VERSION 5.8 ;
BUSBITCHARS "[]" ;
DIVIDERCHAR "/" ;
UNITS
    DATABASE MICRONS 1000 ;
END UNITS

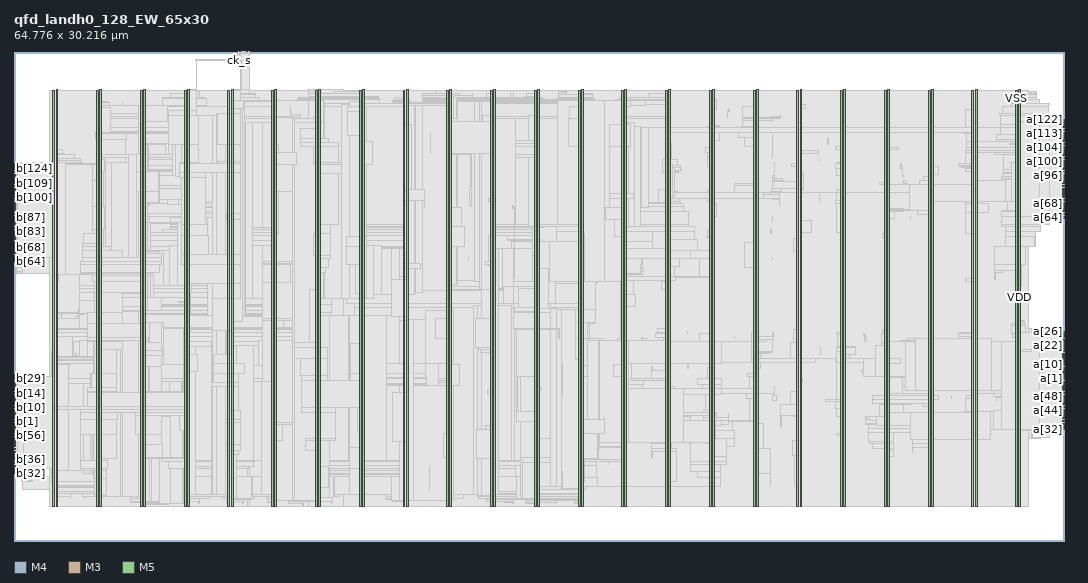
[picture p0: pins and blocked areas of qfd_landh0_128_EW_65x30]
MACRO qfd_landh0_128_EW_65x30
  FOREIGN qfd_landh0_128_EW_65x30 0 0 ;
  CLASS BLOCK ;
  SIZE 64.776 BY 30.216 ;
  PIN a[0]
    DIRECTION INPUT ;
    USE SIGNAL ;
    PORT
      LAYER M4 ;
        RECT  64.692 9.936 64.776 9.96 ;
    END
  END a[0]
  PIN a[100]
    DIRECTION INPUT ;
    USE SIGNAL ;
    PORT
      LAYER M4 ;
        RECT  64.692 23.376 64.776 23.4 ;
    END
  END a[100]
  PIN a[101]
    DIRECTION INPUT ;
    USE SIGNAL ;
    PORT
      LAYER M4 ;
        RECT  64.692 23.472 64.776 23.496 ;
    END
  END a[101]
  PIN a[102]
    DIRECTION INPUT ;
    USE SIGNAL ;
    PORT
      LAYER M4 ;
        RECT  64.692 23.568 64.776 23.592 ;
    END
  END a[102]
  PIN a[103]
    DIRECTION INPUT ;
    USE SIGNAL ;
    PORT
      LAYER M4 ;
        RECT  64.692 23.664 64.776 23.688 ;
    END
  END a[103]
  PIN a[104]
    DIRECTION INPUT ;
    USE SIGNAL ;
    PORT
      LAYER M4 ;
        RECT  64.692 23.76 64.776 23.784 ;
    END
  END a[104]
  PIN a[105]
    DIRECTION INPUT ;
    USE SIGNAL ;
    PORT
      LAYER M4 ;
        RECT  64.692 23.856 64.776 23.88 ;
    END
  END a[105]
  PIN a[106]
    DIRECTION INPUT ;
    USE SIGNAL ;
    PORT
      LAYER M4 ;
        RECT  64.692 23.952 64.776 23.976 ;
    END
  END a[106]
  PIN a[107]
    DIRECTION INPUT ;
    USE SIGNAL ;
    PORT
      LAYER M4 ;
        RECT  64.692 24.048 64.776 24.072 ;
    END
  END a[107]
  PIN a[108]
    DIRECTION INPUT ;
    USE SIGNAL ;
    PORT
      LAYER M4 ;
        RECT  64.692 24.144 64.776 24.168 ;
    END
  END a[108]
  PIN a[109]
    DIRECTION INPUT ;
    USE SIGNAL ;
    PORT
      LAYER M4 ;
        RECT  64.692 24.24 64.776 24.264 ;
    END
  END a[109]
  PIN a[10]
    DIRECTION INPUT ;
    USE SIGNAL ;
    PORT
      LAYER M4 ;
        RECT  64.692 10.896 64.776 10.92 ;
    END
  END a[10]
  PIN a[110]
    DIRECTION INPUT ;
    USE SIGNAL ;
    PORT
      LAYER M4 ;
        RECT  64.692 24.336 64.776 24.36 ;
    END
  END a[110]
  PIN a[111]
    DIRECTION INPUT ;
    USE SIGNAL ;
    PORT
      LAYER M4 ;
        RECT  64.692 24.432 64.776 24.456 ;
    END
  END a[111]
  PIN a[112]
    DIRECTION INPUT ;
    USE SIGNAL ;
    PORT
      LAYER M4 ;
        RECT  64.692 24.528 64.776 24.552 ;
    END
  END a[112]
  PIN a[113]
    DIRECTION INPUT ;
    USE SIGNAL ;
    PORT
      LAYER M4 ;
        RECT  64.692 24.624 64.776 24.648 ;
    END
  END a[113]
  PIN a[114]
    DIRECTION INPUT ;
    USE SIGNAL ;
    PORT
      LAYER M4 ;
        RECT  64.692 24.72 64.776 24.744 ;
    END
  END a[114]
  PIN a[115]
    DIRECTION INPUT ;
    USE SIGNAL ;
    PORT
      LAYER M4 ;
        RECT  64.692 24.816 64.776 24.84 ;
    END
  END a[115]
  PIN a[116]
    DIRECTION INPUT ;
    USE SIGNAL ;
    PORT
      LAYER M4 ;
        RECT  64.692 24.912 64.776 24.936 ;
    END
  END a[116]
  PIN a[117]
    DIRECTION INPUT ;
    USE SIGNAL ;
    PORT
      LAYER M4 ;
        RECT  64.692 25.008 64.776 25.032 ;
    END
  END a[117]
  PIN a[118]
    DIRECTION INPUT ;
    USE SIGNAL ;
    PORT
      LAYER M4 ;
        RECT  64.692 25.104 64.776 25.128 ;
    END
  END a[118]
  PIN a[119]
    DIRECTION INPUT ;
    USE SIGNAL ;
    PORT
      LAYER M4 ;
        RECT  64.692 25.2 64.776 25.224 ;
    END
  END a[119]
  PIN a[11]
    DIRECTION INPUT ;
    USE SIGNAL ;
    PORT
      LAYER M4 ;
        RECT  64.692 10.992 64.776 11.016 ;
    END
  END a[11]
  PIN a[120]
    DIRECTION INPUT ;
    USE SIGNAL ;
    PORT
      LAYER M4 ;
        RECT  64.692 25.296 64.776 25.32 ;
    END
  END a[120]
  PIN a[121]
    DIRECTION INPUT ;
    USE SIGNAL ;
    PORT
      LAYER M4 ;
        RECT  64.692 25.392 64.776 25.416 ;
    END
  END a[121]
  PIN a[122]
    DIRECTION INPUT ;
    USE SIGNAL ;
    PORT
      LAYER M4 ;
        RECT  64.692 25.488 64.776 25.512 ;
    END
  END a[122]
  PIN a[123]
    DIRECTION INPUT ;
    USE SIGNAL ;
    PORT
      LAYER M4 ;
        RECT  64.692 25.584 64.776 25.608 ;
    END
  END a[123]
  PIN a[124]
    DIRECTION INPUT ;
    USE SIGNAL ;
    PORT
      LAYER M4 ;
        RECT  64.692 25.68 64.776 25.704 ;
    END
  END a[124]
  PIN a[125]
    DIRECTION INPUT ;
    USE SIGNAL ;
    PORT
      LAYER M4 ;
        RECT  64.692 25.776 64.776 25.8 ;
    END
  END a[125]
  PIN a[126]
    DIRECTION INPUT ;
    USE SIGNAL ;
    PORT
      LAYER M4 ;
        RECT  64.692 25.872 64.776 25.896 ;
    END
  END a[126]
  PIN a[127]
    DIRECTION INPUT ;
    USE SIGNAL ;
    PORT
      LAYER M4 ;
        RECT  64.692 25.968 64.776 25.992 ;
    END
  END a[127]
  PIN a[12]
    DIRECTION INPUT ;
    USE SIGNAL ;
    PORT
      LAYER M4 ;
        RECT  64.692 11.088 64.776 11.112 ;
    END
  END a[12]
  PIN a[13]
    DIRECTION INPUT ;
    USE SIGNAL ;
    PORT
      LAYER M4 ;
        RECT  64.692 11.184 64.776 11.208 ;
    END
  END a[13]
  PIN a[14]
    DIRECTION INPUT ;
    USE SIGNAL ;
    PORT
      LAYER M4 ;
        RECT  64.692 11.28 64.776 11.304 ;
    END
  END a[14]
  PIN a[15]
    DIRECTION INPUT ;
    USE SIGNAL ;
    PORT
      LAYER M4 ;
        RECT  64.692 11.376 64.776 11.4 ;
    END
  END a[15]
  PIN a[16]
    DIRECTION INPUT ;
    USE SIGNAL ;
    PORT
      LAYER M4 ;
        RECT  64.692 11.472 64.776 11.496 ;
    END
  END a[16]
  PIN a[17]
    DIRECTION INPUT ;
    USE SIGNAL ;
    PORT
      LAYER M4 ;
        RECT  64.692 11.568 64.776 11.592 ;
    END
  END a[17]
  PIN a[18]
    DIRECTION INPUT ;
    USE SIGNAL ;
    PORT
      LAYER M4 ;
        RECT  64.692 11.664 64.776 11.688 ;
    END
  END a[18]
  PIN a[19]
    DIRECTION INPUT ;
    USE SIGNAL ;
    PORT
      LAYER M4 ;
        RECT  64.692 11.76 64.776 11.784 ;
    END
  END a[19]
  PIN a[1]
    DIRECTION INPUT ;
    USE SIGNAL ;
    PORT
      LAYER M4 ;
        RECT  64.692 10.032 64.776 10.056 ;
    END
  END a[1]
  PIN a[20]
    DIRECTION INPUT ;
    USE SIGNAL ;
    PORT
      LAYER M4 ;
        RECT  64.692 11.856 64.776 11.88 ;
    END
  END a[20]
  PIN a[21]
    DIRECTION INPUT ;
    USE SIGNAL ;
    PORT
      LAYER M4 ;
        RECT  64.692 11.952 64.776 11.976 ;
    END
  END a[21]
  PIN a[22]
    DIRECTION INPUT ;
    USE SIGNAL ;
    PORT
      LAYER M4 ;
        RECT  64.692 12.048 64.776 12.072 ;
    END
  END a[22]
  PIN a[23]
    DIRECTION INPUT ;
    USE SIGNAL ;
    PORT
      LAYER M4 ;
        RECT  64.692 12.144 64.776 12.168 ;
    END
  END a[23]
  PIN a[24]
    DIRECTION INPUT ;
    USE SIGNAL ;
    PORT
      LAYER M4 ;
        RECT  64.692 12.24 64.776 12.264 ;
    END
  END a[24]
  PIN a[25]
    DIRECTION INPUT ;
    USE SIGNAL ;
    PORT
      LAYER M4 ;
        RECT  64.692 12.336 64.776 12.36 ;
    END
  END a[25]
  PIN a[26]
    DIRECTION INPUT ;
    USE SIGNAL ;
    PORT
      LAYER M4 ;
        RECT  64.692 12.432 64.776 12.456 ;
    END
  END a[26]
  PIN a[27]
    DIRECTION INPUT ;
    USE SIGNAL ;
    PORT
      LAYER M4 ;
        RECT  64.692 12.528 64.776 12.552 ;
    END
  END a[27]
  PIN a[28]
    DIRECTION INPUT ;
    USE SIGNAL ;
    PORT
      LAYER M4 ;
        RECT  64.692 12.624 64.776 12.648 ;
    END
  END a[28]
  PIN a[29]
    DIRECTION INPUT ;
    USE SIGNAL ;
    PORT
      LAYER M4 ;
        RECT  64.692 12.72 64.776 12.744 ;
    END
  END a[29]
  PIN a[2]
    DIRECTION INPUT ;
    USE SIGNAL ;
    PORT
      LAYER M4 ;
        RECT  64.692 10.128 64.776 10.152 ;
    END
  END a[2]
  PIN a[30]
    DIRECTION INPUT ;
    USE SIGNAL ;
    PORT
      LAYER M4 ;
        RECT  64.692 12.816 64.776 12.84 ;
    END
  END a[30]
  PIN a[31]
    DIRECTION INPUT ;
    USE SIGNAL ;
    PORT
      LAYER M4 ;
        RECT  64.692 12.912 64.776 12.936 ;
    END
  END a[31]
  PIN a[32]
    DIRECTION INPUT ;
    USE SIGNAL ;
    PORT
      LAYER M4 ;
        RECT  64.692 6.864 64.776 6.888 ;
    END
  END a[32]
  PIN a[33]
    DIRECTION INPUT ;
    USE SIGNAL ;
    PORT
      LAYER M4 ;
        RECT  64.692 6.96 64.776 6.984 ;
    END
  END a[33]
  PIN a[34]
    DIRECTION INPUT ;
    USE SIGNAL ;
    PORT
      LAYER M4 ;
        RECT  64.692 7.056 64.776 7.08 ;
    END
  END a[34]
  PIN a[35]
    DIRECTION INPUT ;
    USE SIGNAL ;
    PORT
      LAYER M4 ;
        RECT  64.692 7.152 64.776 7.176 ;
    END
  END a[35]
  PIN a[36]
    DIRECTION INPUT ;
    USE SIGNAL ;
    PORT
      LAYER M4 ;
        RECT  64.692 7.248 64.776 7.272 ;
    END
  END a[36]
  PIN a[37]
    DIRECTION INPUT ;
    USE SIGNAL ;
    PORT
      LAYER M4 ;
        RECT  64.692 7.344 64.776 7.368 ;
    END
  END a[37]
  PIN a[38]
    DIRECTION INPUT ;
    USE SIGNAL ;
    PORT
      LAYER M4 ;
        RECT  64.692 7.44 64.776 7.464 ;
    END
  END a[38]
  PIN a[39]
    DIRECTION INPUT ;
    USE SIGNAL ;
    PORT
      LAYER M4 ;
        RECT  64.692 7.536 64.776 7.56 ;
    END
  END a[39]
  PIN a[3]
    DIRECTION INPUT ;
    USE SIGNAL ;
    PORT
      LAYER M4 ;
        RECT  64.692 10.224 64.776 10.248 ;
    END
  END a[3]
  PIN a[40]
    DIRECTION INPUT ;
    USE SIGNAL ;
    PORT
      LAYER M4 ;
        RECT  64.692 7.632 64.776 7.656 ;
    END
  END a[40]
  PIN a[41]
    DIRECTION INPUT ;
    USE SIGNAL ;
    PORT
      LAYER M4 ;
        RECT  64.692 7.728 64.776 7.752 ;
    END
  END a[41]
  PIN a[42]
    DIRECTION INPUT ;
    USE SIGNAL ;
    PORT
      LAYER M4 ;
        RECT  64.692 7.824 64.776 7.848 ;
    END
  END a[42]
  PIN a[43]
    DIRECTION INPUT ;
    USE SIGNAL ;
    PORT
      LAYER M4 ;
        RECT  64.692 7.92 64.776 7.944 ;
    END
  END a[43]
  PIN a[44]
    DIRECTION INPUT ;
    USE SIGNAL ;
    PORT
      LAYER M4 ;
        RECT  64.692 8.016 64.776 8.04 ;
    END
  END a[44]
  PIN a[45]
    DIRECTION INPUT ;
    USE SIGNAL ;
    PORT
      LAYER M4 ;
        RECT  64.692 8.112 64.776 8.136 ;
    END
  END a[45]
  PIN a[46]
    DIRECTION INPUT ;
    USE SIGNAL ;
    PORT
      LAYER M4 ;
        RECT  64.692 8.208 64.776 8.232 ;
    END
  END a[46]
  PIN a[47]
    DIRECTION INPUT ;
    USE SIGNAL ;
    PORT
      LAYER M4 ;
        RECT  64.692 8.304 64.776 8.328 ;
    END
  END a[47]
  PIN a[48]
    DIRECTION INPUT ;
    USE SIGNAL ;
    PORT
      LAYER M4 ;
        RECT  64.692 8.4 64.776 8.424 ;
    END
  END a[48]
  PIN a[49]
    DIRECTION INPUT ;
    USE SIGNAL ;
    PORT
      LAYER M4 ;
        RECT  64.692 8.496 64.776 8.52 ;
    END
  END a[49]
  PIN a[4]
    DIRECTION INPUT ;
    USE SIGNAL ;
    PORT
      LAYER M4 ;
        RECT  64.692 10.32 64.776 10.344 ;
    END
  END a[4]
  PIN a[50]
    DIRECTION INPUT ;
    USE SIGNAL ;
    PORT
      LAYER M4 ;
        RECT  64.692 8.592 64.776 8.616 ;
    END
  END a[50]
  PIN a[51]
    DIRECTION INPUT ;
    USE SIGNAL ;
    PORT
      LAYER M4 ;
        RECT  64.692 8.688 64.776 8.712 ;
    END
  END a[51]
  PIN a[52]
    DIRECTION INPUT ;
    USE SIGNAL ;
    PORT
      LAYER M4 ;
        RECT  64.692 8.784 64.776 8.808 ;
    END
  END a[52]
  PIN a[53]
    DIRECTION INPUT ;
    USE SIGNAL ;
    PORT
      LAYER M4 ;
        RECT  64.692 8.88 64.776 8.904 ;
    END
  END a[53]
  PIN a[54]
    DIRECTION INPUT ;
    USE SIGNAL ;
    PORT
      LAYER M4 ;
        RECT  64.692 8.976 64.776 9 ;
    END
  END a[54]
  PIN a[55]
    DIRECTION INPUT ;
    USE SIGNAL ;
    PORT
      LAYER M4 ;
        RECT  64.692 9.072 64.776 9.096 ;
    END
  END a[55]
  PIN a[56]
    DIRECTION INPUT ;
    USE SIGNAL ;
    PORT
      LAYER M4 ;
        RECT  64.692 9.168 64.776 9.192 ;
    END
  END a[56]
  PIN a[57]
    DIRECTION INPUT ;
    USE SIGNAL ;
    PORT
      LAYER M4 ;
        RECT  64.692 9.264 64.776 9.288 ;
    END
  END a[57]
  PIN a[58]
    DIRECTION INPUT ;
    USE SIGNAL ;
    PORT
      LAYER M4 ;
        RECT  64.692 9.36 64.776 9.384 ;
    END
  END a[58]
  PIN a[59]
    DIRECTION INPUT ;
    USE SIGNAL ;
    PORT
      LAYER M4 ;
        RECT  64.692 9.456 64.776 9.48 ;
    END
  END a[59]
  PIN a[5]
    DIRECTION INPUT ;
    USE SIGNAL ;
    PORT
      LAYER M4 ;
        RECT  64.692 10.416 64.776 10.44 ;
    END
  END a[5]
  PIN a[60]
    DIRECTION INPUT ;
    USE SIGNAL ;
    PORT
      LAYER M4 ;
        RECT  64.692 9.552 64.776 9.576 ;
    END
  END a[60]
  PIN a[61]
    DIRECTION INPUT ;
    USE SIGNAL ;
    PORT
      LAYER M4 ;
        RECT  64.692 9.648 64.776 9.672 ;
    END
  END a[61]
  PIN a[62]
    DIRECTION INPUT ;
    USE SIGNAL ;
    PORT
      LAYER M4 ;
        RECT  64.692 9.744 64.776 9.768 ;
    END
  END a[62]
  PIN a[63]
    DIRECTION INPUT ;
    USE SIGNAL ;
    PORT
      LAYER M4 ;
        RECT  64.692 9.84 64.776 9.864 ;
    END
  END a[63]
  PIN a[64]
    DIRECTION INPUT ;
    USE SIGNAL ;
    PORT
      LAYER M4 ;
        RECT  64.692 19.92 64.776 19.944 ;
    END
  END a[64]
  PIN a[65]
    DIRECTION INPUT ;
    USE SIGNAL ;
    PORT
      LAYER M4 ;
        RECT  64.692 20.016 64.776 20.04 ;
    END
  END a[65]
  PIN a[66]
    DIRECTION INPUT ;
    USE SIGNAL ;
    PORT
      LAYER M4 ;
        RECT  64.692 20.112 64.776 20.136 ;
    END
  END a[66]
  PIN a[67]
    DIRECTION INPUT ;
    USE SIGNAL ;
    PORT
      LAYER M4 ;
        RECT  64.692 20.208 64.776 20.232 ;
    END
  END a[67]
  PIN a[68]
    DIRECTION INPUT ;
    USE SIGNAL ;
    PORT
      LAYER M4 ;
        RECT  64.692 20.304 64.776 20.328 ;
    END
  END a[68]
  PIN a[69]
    DIRECTION INPUT ;
    USE SIGNAL ;
    PORT
      LAYER M4 ;
        RECT  64.692 20.4 64.776 20.424 ;
    END
  END a[69]
  PIN a[6]
    DIRECTION INPUT ;
    USE SIGNAL ;
    PORT
      LAYER M4 ;
        RECT  64.692 10.512 64.776 10.536 ;
    END
  END a[6]
  PIN a[70]
    DIRECTION INPUT ;
    USE SIGNAL ;
    PORT
      LAYER M4 ;
        RECT  64.692 20.496 64.776 20.52 ;
    END
  END a[70]
  PIN a[71]
    DIRECTION INPUT ;
    USE SIGNAL ;
    PORT
      LAYER M4 ;
        RECT  64.692 20.592 64.776 20.616 ;
    END
  END a[71]
  PIN a[72]
    DIRECTION INPUT ;
    USE SIGNAL ;
    PORT
      LAYER M4 ;
        RECT  64.692 20.688 64.776 20.712 ;
    END
  END a[72]
  PIN a[73]
    DIRECTION INPUT ;
    USE SIGNAL ;
    PORT
      LAYER M4 ;
        RECT  64.692 20.784 64.776 20.808 ;
    END
  END a[73]
  PIN a[74]
    DIRECTION INPUT ;
    USE SIGNAL ;
    PORT
      LAYER M4 ;
        RECT  64.692 20.88 64.776 20.904 ;
    END
  END a[74]
  PIN a[75]
    DIRECTION INPUT ;
    USE SIGNAL ;
    PORT
      LAYER M4 ;
        RECT  64.692 20.976 64.776 21 ;
    END
  END a[75]
  PIN a[76]
    DIRECTION INPUT ;
    USE SIGNAL ;
    PORT
      LAYER M4 ;
        RECT  64.692 21.072 64.776 21.096 ;
    END
  END a[76]
  PIN a[77]
    DIRECTION INPUT ;
    USE SIGNAL ;
    PORT
      LAYER M4 ;
        RECT  64.692 21.168 64.776 21.192 ;
    END
  END a[77]
  PIN a[78]
    DIRECTION INPUT ;
    USE SIGNAL ;
    PORT
      LAYER M4 ;
        RECT  64.692 21.264 64.776 21.288 ;
    END
  END a[78]
  PIN a[79]
    DIRECTION INPUT ;
    USE SIGNAL ;
    PORT
      LAYER M4 ;
        RECT  64.692 21.36 64.776 21.384 ;
    END
  END a[79]
  PIN a[7]
    DIRECTION INPUT ;
    USE SIGNAL ;
    PORT
      LAYER M4 ;
        RECT  64.692 10.608 64.776 10.632 ;
    END
  END a[7]
  PIN a[80]
    DIRECTION INPUT ;
    USE SIGNAL ;
    PORT
      LAYER M4 ;
        RECT  64.692 21.456 64.776 21.48 ;
    END
  END a[80]
  PIN a[81]
    DIRECTION INPUT ;
    USE SIGNAL ;
    PORT
      LAYER M4 ;
        RECT  64.692 21.552 64.776 21.576 ;
    END
  END a[81]
  PIN a[82]
    DIRECTION INPUT ;
    USE SIGNAL ;
    PORT
      LAYER M4 ;
        RECT  64.692 21.648 64.776 21.672 ;
    END
  END a[82]
  PIN a[83]
    DIRECTION INPUT ;
    USE SIGNAL ;
    PORT
      LAYER M4 ;
        RECT  64.692 21.744 64.776 21.768 ;
    END
  END a[83]
  PIN a[84]
    DIRECTION INPUT ;
    USE SIGNAL ;
    PORT
      LAYER M4 ;
        RECT  64.692 21.84 64.776 21.864 ;
    END
  END a[84]
  PIN a[85]
    DIRECTION INPUT ;
    USE SIGNAL ;
    PORT
      LAYER M4 ;
        RECT  64.692 21.936 64.776 21.96 ;
    END
  END a[85]
  PIN a[86]
    DIRECTION INPUT ;
    USE SIGNAL ;
    PORT
      LAYER M4 ;
        RECT  64.692 22.032 64.776 22.056 ;
    END
  END a[86]
  PIN a[87]
    DIRECTION INPUT ;
    USE SIGNAL ;
    PORT
      LAYER M4 ;
        RECT  64.692 22.128 64.776 22.152 ;
    END
  END a[87]
  PIN a[88]
    DIRECTION INPUT ;
    USE SIGNAL ;
    PORT
      LAYER M4 ;
        RECT  64.692 22.224 64.776 22.248 ;
    END
  END a[88]
  PIN a[89]
    DIRECTION INPUT ;
    USE SIGNAL ;
    PORT
      LAYER M4 ;
        RECT  64.692 22.32 64.776 22.344 ;
    END
  END a[89]
  PIN a[8]
    DIRECTION INPUT ;
    USE SIGNAL ;
    PORT
      LAYER M4 ;
        RECT  64.692 10.704 64.776 10.728 ;
    END
  END a[8]
  PIN a[90]
    DIRECTION INPUT ;
    USE SIGNAL ;
    PORT
      LAYER M4 ;
        RECT  64.692 22.416 64.776 22.44 ;
    END
  END a[90]
  PIN a[91]
    DIRECTION INPUT ;
    USE SIGNAL ;
    PORT
      LAYER M4 ;
        RECT  64.692 22.512 64.776 22.536 ;
    END
  END a[91]
  PIN a[92]
    DIRECTION INPUT ;
    USE SIGNAL ;
    PORT
      LAYER M4 ;
        RECT  64.692 22.608 64.776 22.632 ;
    END
  END a[92]
  PIN a[93]
    DIRECTION INPUT ;
    USE SIGNAL ;
    PORT
      LAYER M4 ;
        RECT  64.692 22.704 64.776 22.728 ;
    END
  END a[93]
  PIN a[94]
    DIRECTION INPUT ;
    USE SIGNAL ;
    PORT
      LAYER M4 ;
        RECT  64.692 22.8 64.776 22.824 ;
    END
  END a[94]
  PIN a[95]
    DIRECTION INPUT ;
    USE SIGNAL ;
    PORT
      LAYER M4 ;
        RECT  64.692 22.896 64.776 22.92 ;
    END
  END a[95]
  PIN a[96]
    DIRECTION INPUT ;
    USE SIGNAL ;
    PORT
      LAYER M4 ;
        RECT  64.692 22.992 64.776 23.016 ;
    END
  END a[96]
  PIN a[97]
    DIRECTION INPUT ;
    USE SIGNAL ;
    PORT
      LAYER M4 ;
        RECT  64.692 23.088 64.776 23.112 ;
    END
  END a[97]
  PIN a[98]
    DIRECTION INPUT ;
    USE SIGNAL ;
    PORT
      LAYER M4 ;
        RECT  64.692 23.184 64.776 23.208 ;
    END
  END a[98]
  PIN a[99]
    DIRECTION INPUT ;
    USE SIGNAL ;
    PORT
      LAYER M4 ;
        RECT  64.692 23.28 64.776 23.304 ;
    END
  END a[99]
  PIN a[9]
    DIRECTION INPUT ;
    USE SIGNAL ;
    PORT
      LAYER M4 ;
        RECT  64.692 10.8 64.776 10.824 ;
    END
  END a[9]
  PIN b[0]
    DIRECTION OUTPUT ;
    USE SIGNAL ;
    PORT
      LAYER M4 ;
        RECT  0 7.248 0.084 7.272 ;
    END
  END b[0]
  PIN b[100]
    DIRECTION OUTPUT ;
    USE SIGNAL ;
    PORT
      LAYER M4 ;
        RECT  0 20.688 0.084 20.712 ;
    END
  END b[100]
  PIN b[101]
    DIRECTION OUTPUT ;
    USE SIGNAL ;
    PORT
      LAYER M4 ;
        RECT  0 20.784 0.084 20.808 ;
    END
  END b[101]
  PIN b[102]
    DIRECTION OUTPUT ;
    USE SIGNAL ;
    PORT
      LAYER M4 ;
        RECT  0 20.88 0.084 20.904 ;
    END
  END b[102]
  PIN b[103]
    DIRECTION OUTPUT ;
    USE SIGNAL ;
    PORT
      LAYER M4 ;
        RECT  0 20.976 0.084 21 ;
    END
  END b[103]
  PIN b[104]
    DIRECTION OUTPUT ;
    USE SIGNAL ;
    PORT
      LAYER M4 ;
        RECT  0 21.072 0.084 21.096 ;
    END
  END b[104]
  PIN b[105]
    DIRECTION OUTPUT ;
    USE SIGNAL ;
    PORT
      LAYER M4 ;
        RECT  0 21.168 0.084 21.192 ;
    END
  END b[105]
  PIN b[106]
    DIRECTION OUTPUT ;
    USE SIGNAL ;
    PORT
      LAYER M4 ;
        RECT  0 21.264 0.084 21.288 ;
    END
  END b[106]
  PIN b[107]
    DIRECTION OUTPUT ;
    USE SIGNAL ;
    PORT
      LAYER M4 ;
        RECT  0 21.36 0.084 21.384 ;
    END
  END b[107]
  PIN b[108]
    DIRECTION OUTPUT ;
    USE SIGNAL ;
    PORT
      LAYER M4 ;
        RECT  0 21.456 0.084 21.48 ;
    END
  END b[108]
  PIN b[109]
    DIRECTION OUTPUT ;
    USE SIGNAL ;
    PORT
      LAYER M4 ;
        RECT  0 21.552 0.084 21.576 ;
    END
  END b[109]
  PIN b[10]
    DIRECTION OUTPUT ;
    USE SIGNAL ;
    PORT
      LAYER M4 ;
        RECT  0 8.208 0.084 8.232 ;
    END
  END b[10]
  PIN b[110]
    DIRECTION OUTPUT ;
    USE SIGNAL ;
    PORT
      LAYER M4 ;
        RECT  0 21.648 0.084 21.672 ;
    END
  END b[110]
  PIN b[111]
    DIRECTION OUTPUT ;
    USE SIGNAL ;
    PORT
      LAYER M4 ;
        RECT  0 21.744 0.084 21.768 ;
    END
  END b[111]
  PIN b[112]
    DIRECTION OUTPUT ;
    USE SIGNAL ;
    PORT
      LAYER M4 ;
        RECT  0 21.84 0.084 21.864 ;
    END
  END b[112]
  PIN b[113]
    DIRECTION OUTPUT ;
    USE SIGNAL ;
    PORT
      LAYER M4 ;
        RECT  0 21.936 0.084 21.96 ;
    END
  END b[113]
  PIN b[114]
    DIRECTION OUTPUT ;
    USE SIGNAL ;
    PORT
      LAYER M4 ;
        RECT  0 22.032 0.084 22.056 ;
    END
  END b[114]
  PIN b[115]
    DIRECTION OUTPUT ;
    USE SIGNAL ;
    PORT
      LAYER M4 ;
        RECT  0 22.128 0.084 22.152 ;
    END
  END b[115]
  PIN b[116]
    DIRECTION OUTPUT ;
    USE SIGNAL ;
    PORT
      LAYER M4 ;
        RECT  0 22.224 0.084 22.248 ;
    END
  END b[116]
  PIN b[117]
    DIRECTION OUTPUT ;
    USE SIGNAL ;
    PORT
      LAYER M4 ;
        RECT  0 22.32 0.084 22.344 ;
    END
  END b[117]
  PIN b[118]
    DIRECTION OUTPUT ;
    USE SIGNAL ;
    PORT
      LAYER M4 ;
        RECT  0 22.416 0.084 22.44 ;
    END
  END b[118]
  PIN b[119]
    DIRECTION OUTPUT ;
    USE SIGNAL ;
    PORT
      LAYER M4 ;
        RECT  0 22.512 0.084 22.536 ;
    END
  END b[119]
  PIN b[11]
    DIRECTION OUTPUT ;
    USE SIGNAL ;
    PORT
      LAYER M4 ;
        RECT  0 8.304 0.084 8.328 ;
    END
  END b[11]
  PIN b[120]
    DIRECTION OUTPUT ;
    USE SIGNAL ;
    PORT
      LAYER M4 ;
        RECT  0 22.608 0.084 22.632 ;
    END
  END b[120]
  PIN b[121]
    DIRECTION OUTPUT ;
    USE SIGNAL ;
    PORT
      LAYER M4 ;
        RECT  0 22.704 0.084 22.728 ;
    END
  END b[121]
  PIN b[122]
    DIRECTION OUTPUT ;
    USE SIGNAL ;
    PORT
      LAYER M4 ;
        RECT  0 22.8 0.084 22.824 ;
    END
  END b[122]
  PIN b[123]
    DIRECTION OUTPUT ;
    USE SIGNAL ;
    PORT
      LAYER M4 ;
        RECT  0 22.896 0.084 22.92 ;
    END
  END b[123]
  PIN b[124]
    DIRECTION OUTPUT ;
    USE SIGNAL ;
    PORT
      LAYER M4 ;
        RECT  0 22.992 0.084 23.016 ;
    END
  END b[124]
  PIN b[125]
    DIRECTION OUTPUT ;
    USE SIGNAL ;
    PORT
      LAYER M4 ;
        RECT  0 23.088 0.084 23.112 ;
    END
  END b[125]
  PIN b[126]
    DIRECTION OUTPUT ;
    USE SIGNAL ;
    PORT
      LAYER M4 ;
        RECT  0 23.184 0.084 23.208 ;
    END
  END b[126]
  PIN b[127]
    DIRECTION OUTPUT ;
    USE SIGNAL ;
    PORT
      LAYER M4 ;
        RECT  0 23.28 0.084 23.304 ;
    END
  END b[127]
  PIN b[12]
    DIRECTION OUTPUT ;
    USE SIGNAL ;
    PORT
      LAYER M4 ;
        RECT  0 8.4 0.084 8.424 ;
    END
  END b[12]
  PIN b[13]
    DIRECTION OUTPUT ;
    USE SIGNAL ;
    PORT
      LAYER M4 ;
        RECT  0 8.496 0.084 8.52 ;
    END
  END b[13]
  PIN b[14]
    DIRECTION OUTPUT ;
    USE SIGNAL ;
    PORT
      LAYER M4 ;
        RECT  0 8.592 0.084 8.616 ;
    END
  END b[14]
  PIN b[15]
    DIRECTION OUTPUT ;
    USE SIGNAL ;
    PORT
      LAYER M4 ;
        RECT  0 8.688 0.084 8.712 ;
    END
  END b[15]
  PIN b[16]
    DIRECTION OUTPUT ;
    USE SIGNAL ;
    PORT
      LAYER M4 ;
        RECT  0 8.784 0.084 8.808 ;
    END
  END b[16]
  PIN b[17]
    DIRECTION OUTPUT ;
    USE SIGNAL ;
    PORT
      LAYER M4 ;
        RECT  0 8.88 0.084 8.904 ;
    END
  END b[17]
  PIN b[18]
    DIRECTION OUTPUT ;
    USE SIGNAL ;
    PORT
      LAYER M4 ;
        RECT  0 8.976 0.084 9 ;
    END
  END b[18]
  PIN b[19]
    DIRECTION OUTPUT ;
    USE SIGNAL ;
    PORT
      LAYER M4 ;
        RECT  0 9.072 0.084 9.096 ;
    END
  END b[19]
  PIN b[1]
    DIRECTION OUTPUT ;
    USE SIGNAL ;
    PORT
      LAYER M4 ;
        RECT  0 7.344 0.084 7.368 ;
    END
  END b[1]
  PIN b[20]
    DIRECTION OUTPUT ;
    USE SIGNAL ;
    PORT
      LAYER M4 ;
        RECT  0 9.168 0.084 9.192 ;
    END
  END b[20]
  PIN b[21]
    DIRECTION OUTPUT ;
    USE SIGNAL ;
    PORT
      LAYER M4 ;
        RECT  0 9.264 0.084 9.288 ;
    END
  END b[21]
  PIN b[22]
    DIRECTION OUTPUT ;
    USE SIGNAL ;
    PORT
      LAYER M4 ;
        RECT  0 9.36 0.084 9.384 ;
    END
  END b[22]
  PIN b[23]
    DIRECTION OUTPUT ;
    USE SIGNAL ;
    PORT
      LAYER M4 ;
        RECT  0 9.456 0.084 9.48 ;
    END
  END b[23]
  PIN b[24]
    DIRECTION OUTPUT ;
    USE SIGNAL ;
    PORT
      LAYER M4 ;
        RECT  0 9.552 0.084 9.576 ;
    END
  END b[24]
  PIN b[25]
    DIRECTION OUTPUT ;
    USE SIGNAL ;
    PORT
      LAYER M4 ;
        RECT  0 9.648 0.084 9.672 ;
    END
  END b[25]
  PIN b[26]
    DIRECTION OUTPUT ;
    USE SIGNAL ;
    PORT
      LAYER M4 ;
        RECT  0 9.744 0.084 9.768 ;
    END
  END b[26]
  PIN b[27]
    DIRECTION OUTPUT ;
    USE SIGNAL ;
    PORT
      LAYER M4 ;
        RECT  0 9.84 0.084 9.864 ;
    END
  END b[27]
  PIN b[28]
    DIRECTION OUTPUT ;
    USE SIGNAL ;
    PORT
      LAYER M4 ;
        RECT  0 9.936 0.084 9.96 ;
    END
  END b[28]
  PIN b[29]
    DIRECTION OUTPUT ;
    USE SIGNAL ;
    PORT
      LAYER M4 ;
        RECT  0 10.032 0.084 10.056 ;
    END
  END b[29]
  PIN b[2]
    DIRECTION OUTPUT ;
    USE SIGNAL ;
    PORT
      LAYER M4 ;
        RECT  0 7.44 0.084 7.464 ;
    END
  END b[2]
  PIN b[30]
    DIRECTION OUTPUT ;
    USE SIGNAL ;
    PORT
      LAYER M4 ;
        RECT  0 10.128 0.084 10.152 ;
    END
  END b[30]
  PIN b[31]
    DIRECTION OUTPUT ;
    USE SIGNAL ;
    PORT
      LAYER M4 ;
        RECT  0 10.224 0.084 10.248 ;
    END
  END b[31]
  PIN b[32]
    DIRECTION OUTPUT ;
    USE SIGNAL ;
    PORT
      LAYER M4 ;
        RECT  0 4.176 0.084 4.2 ;
    END
  END b[32]
  PIN b[33]
    DIRECTION OUTPUT ;
    USE SIGNAL ;
    PORT
      LAYER M4 ;
        RECT  0 4.272 0.084 4.296 ;
    END
  END b[33]
  PIN b[34]
    DIRECTION OUTPUT ;
    USE SIGNAL ;
    PORT
      LAYER M4 ;
        RECT  0 4.368 0.084 4.392 ;
    END
  END b[34]
  PIN b[35]
    DIRECTION OUTPUT ;
    USE SIGNAL ;
    PORT
      LAYER M4 ;
        RECT  0 4.464 0.084 4.488 ;
    END
  END b[35]
  PIN b[36]
    DIRECTION OUTPUT ;
    USE SIGNAL ;
    PORT
      LAYER M4 ;
        RECT  0 4.56 0.084 4.584 ;
    END
  END b[36]
  PIN b[37]
    DIRECTION OUTPUT ;
    USE SIGNAL ;
    PORT
      LAYER M4 ;
        RECT  0 4.656 0.084 4.68 ;
    END
  END b[37]
  PIN b[38]
    DIRECTION OUTPUT ;
    USE SIGNAL ;
    PORT
      LAYER M4 ;
        RECT  0 4.752 0.084 4.776 ;
    END
  END b[38]
  PIN b[39]
    DIRECTION OUTPUT ;
    USE SIGNAL ;
    PORT
      LAYER M4 ;
        RECT  0 4.848 0.084 4.872 ;
    END
  END b[39]
  PIN b[3]
    DIRECTION OUTPUT ;
    USE SIGNAL ;
    PORT
      LAYER M4 ;
        RECT  0 7.536 0.084 7.56 ;
    END
  END b[3]
  PIN b[40]
    DIRECTION OUTPUT ;
    USE SIGNAL ;
    PORT
      LAYER M4 ;
        RECT  0 4.944 0.084 4.968 ;
    END
  END b[40]
  PIN b[41]
    DIRECTION OUTPUT ;
    USE SIGNAL ;
    PORT
      LAYER M4 ;
        RECT  0 5.04 0.084 5.064 ;
    END
  END b[41]
  PIN b[42]
    DIRECTION OUTPUT ;
    USE SIGNAL ;
    PORT
      LAYER M4 ;
        RECT  0 5.136 0.084 5.16 ;
    END
  END b[42]
  PIN b[43]
    DIRECTION OUTPUT ;
    USE SIGNAL ;
    PORT
      LAYER M4 ;
        RECT  0 5.232 0.084 5.256 ;
    END
  END b[43]
  PIN b[44]
    DIRECTION OUTPUT ;
    USE SIGNAL ;
    PORT
      LAYER M4 ;
        RECT  0 5.328 0.084 5.352 ;
    END
  END b[44]
  PIN b[45]
    DIRECTION OUTPUT ;
    USE SIGNAL ;
    PORT
      LAYER M4 ;
        RECT  0 5.424 0.084 5.448 ;
    END
  END b[45]
  PIN b[46]
    DIRECTION OUTPUT ;
    USE SIGNAL ;
    PORT
      LAYER M4 ;
        RECT  0 5.52 0.084 5.544 ;
    END
  END b[46]
  PIN b[47]
    DIRECTION OUTPUT ;
    USE SIGNAL ;
    PORT
      LAYER M4 ;
        RECT  0 5.616 0.084 5.64 ;
    END
  END b[47]
  PIN b[48]
    DIRECTION OUTPUT ;
    USE SIGNAL ;
    PORT
      LAYER M4 ;
        RECT  0 5.712 0.084 5.736 ;
    END
  END b[48]
  PIN b[49]
    DIRECTION OUTPUT ;
    USE SIGNAL ;
    PORT
      LAYER M4 ;
        RECT  0 5.808 0.084 5.832 ;
    END
  END b[49]
  PIN b[4]
    DIRECTION OUTPUT ;
    USE SIGNAL ;
    PORT
      LAYER M4 ;
        RECT  0 7.632 0.084 7.656 ;
    END
  END b[4]
  PIN b[50]
    DIRECTION OUTPUT ;
    USE SIGNAL ;
    PORT
      LAYER M4 ;
        RECT  0 5.904 0.084 5.928 ;
    END
  END b[50]
  PIN b[51]
    DIRECTION OUTPUT ;
    USE SIGNAL ;
    PORT
      LAYER M4 ;
        RECT  0 6 0.084 6.024 ;
    END
  END b[51]
  PIN b[52]
    DIRECTION OUTPUT ;
    USE SIGNAL ;
    PORT
      LAYER M4 ;
        RECT  0 6.096 0.084 6.12 ;
    END
  END b[52]
  PIN b[53]
    DIRECTION OUTPUT ;
    USE SIGNAL ;
    PORT
      LAYER M4 ;
        RECT  0 6.192 0.084 6.216 ;
    END
  END b[53]
  PIN b[54]
    DIRECTION OUTPUT ;
    USE SIGNAL ;
    PORT
      LAYER M4 ;
        RECT  0 6.288 0.084 6.312 ;
    END
  END b[54]
  PIN b[55]
    DIRECTION OUTPUT ;
    USE SIGNAL ;
    PORT
      LAYER M4 ;
        RECT  0 6.384 0.084 6.408 ;
    END
  END b[55]
  PIN b[56]
    DIRECTION OUTPUT ;
    USE SIGNAL ;
    PORT
      LAYER M4 ;
        RECT  0 6.48 0.084 6.504 ;
    END
  END b[56]
  PIN b[57]
    DIRECTION OUTPUT ;
    USE SIGNAL ;
    PORT
      LAYER M4 ;
        RECT  0 6.576 0.084 6.6 ;
    END
  END b[57]
  PIN b[58]
    DIRECTION OUTPUT ;
    USE SIGNAL ;
    PORT
      LAYER M4 ;
        RECT  0 6.672 0.084 6.696 ;
    END
  END b[58]
  PIN b[59]
    DIRECTION OUTPUT ;
    USE SIGNAL ;
    PORT
      LAYER M4 ;
        RECT  0 6.768 0.084 6.792 ;
    END
  END b[59]
  PIN b[5]
    DIRECTION OUTPUT ;
    USE SIGNAL ;
    PORT
      LAYER M4 ;
        RECT  0 7.728 0.084 7.752 ;
    END
  END b[5]
  PIN b[60]
    DIRECTION OUTPUT ;
    USE SIGNAL ;
    PORT
      LAYER M4 ;
        RECT  0 6.864 0.084 6.888 ;
    END
  END b[60]
  PIN b[61]
    DIRECTION OUTPUT ;
    USE SIGNAL ;
    PORT
      LAYER M4 ;
        RECT  0 6.96 0.084 6.984 ;
    END
  END b[61]
  PIN b[62]
    DIRECTION OUTPUT ;
    USE SIGNAL ;
    PORT
      LAYER M4 ;
        RECT  0 7.056 0.084 7.08 ;
    END
  END b[62]
  PIN b[63]
    DIRECTION OUTPUT ;
    USE SIGNAL ;
    PORT
      LAYER M4 ;
        RECT  0 7.152 0.084 7.176 ;
    END
  END b[63]
  PIN b[64]
    DIRECTION OUTPUT ;
    USE SIGNAL ;
    PORT
      LAYER M4 ;
        RECT  0 17.232 0.084 17.256 ;
    END
  END b[64]
  PIN b[65]
    DIRECTION OUTPUT ;
    USE SIGNAL ;
    PORT
      LAYER M4 ;
        RECT  0 17.328 0.084 17.352 ;
    END
  END b[65]
  PIN b[66]
    DIRECTION OUTPUT ;
    USE SIGNAL ;
    PORT
      LAYER M4 ;
        RECT  0 17.424 0.084 17.448 ;
    END
  END b[66]
  PIN b[67]
    DIRECTION OUTPUT ;
    USE SIGNAL ;
    PORT
      LAYER M4 ;
        RECT  0 17.52 0.084 17.544 ;
    END
  END b[67]
  PIN b[68]
    DIRECTION OUTPUT ;
    USE SIGNAL ;
    PORT
      LAYER M4 ;
        RECT  0 17.616 0.084 17.64 ;
    END
  END b[68]
  PIN b[69]
    DIRECTION OUTPUT ;
    USE SIGNAL ;
    PORT
      LAYER M4 ;
        RECT  0 17.712 0.084 17.736 ;
    END
  END b[69]
  PIN b[6]
    DIRECTION OUTPUT ;
    USE SIGNAL ;
    PORT
      LAYER M4 ;
        RECT  0 7.824 0.084 7.848 ;
    END
  END b[6]
  PIN b[70]
    DIRECTION OUTPUT ;
    USE SIGNAL ;
    PORT
      LAYER M4 ;
        RECT  0 17.808 0.084 17.832 ;
    END
  END b[70]
  PIN b[71]
    DIRECTION OUTPUT ;
    USE SIGNAL ;
    PORT
      LAYER M4 ;
        RECT  0 17.904 0.084 17.928 ;
    END
  END b[71]
  PIN b[72]
    DIRECTION OUTPUT ;
    USE SIGNAL ;
    PORT
      LAYER M4 ;
        RECT  0 18 0.084 18.024 ;
    END
  END b[72]
  PIN b[73]
    DIRECTION OUTPUT ;
    USE SIGNAL ;
    PORT
      LAYER M4 ;
        RECT  0 18.096 0.084 18.12 ;
    END
  END b[73]
  PIN b[74]
    DIRECTION OUTPUT ;
    USE SIGNAL ;
    PORT
      LAYER M4 ;
        RECT  0 18.192 0.084 18.216 ;
    END
  END b[74]
  PIN b[75]
    DIRECTION OUTPUT ;
    USE SIGNAL ;
    PORT
      LAYER M4 ;
        RECT  0 18.288 0.084 18.312 ;
    END
  END b[75]
  PIN b[76]
    DIRECTION OUTPUT ;
    USE SIGNAL ;
    PORT
      LAYER M4 ;
        RECT  0 18.384 0.084 18.408 ;
    END
  END b[76]
  PIN b[77]
    DIRECTION OUTPUT ;
    USE SIGNAL ;
    PORT
      LAYER M4 ;
        RECT  0 18.48 0.084 18.504 ;
    END
  END b[77]
  PIN b[78]
    DIRECTION OUTPUT ;
    USE SIGNAL ;
    PORT
      LAYER M4 ;
        RECT  0 18.576 0.084 18.6 ;
    END
  END b[78]
  PIN b[79]
    DIRECTION OUTPUT ;
    USE SIGNAL ;
    PORT
      LAYER M4 ;
        RECT  0 18.672 0.084 18.696 ;
    END
  END b[79]
  PIN b[7]
    DIRECTION OUTPUT ;
    USE SIGNAL ;
    PORT
      LAYER M4 ;
        RECT  0 7.92 0.084 7.944 ;
    END
  END b[7]
  PIN b[80]
    DIRECTION OUTPUT ;
    USE SIGNAL ;
    PORT
      LAYER M4 ;
        RECT  0 18.768 0.084 18.792 ;
    END
  END b[80]
  PIN b[81]
    DIRECTION OUTPUT ;
    USE SIGNAL ;
    PORT
      LAYER M4 ;
        RECT  0 18.864 0.084 18.888 ;
    END
  END b[81]
  PIN b[82]
    DIRECTION OUTPUT ;
    USE SIGNAL ;
    PORT
      LAYER M4 ;
        RECT  0 18.96 0.084 18.984 ;
    END
  END b[82]
  PIN b[83]
    DIRECTION OUTPUT ;
    USE SIGNAL ;
    PORT
      LAYER M4 ;
        RECT  0 19.056 0.084 19.08 ;
    END
  END b[83]
  PIN b[84]
    DIRECTION OUTPUT ;
    USE SIGNAL ;
    PORT
      LAYER M4 ;
        RECT  0 19.152 0.084 19.176 ;
    END
  END b[84]
  PIN b[85]
    DIRECTION OUTPUT ;
    USE SIGNAL ;
    PORT
      LAYER M4 ;
        RECT  0 19.248 0.084 19.272 ;
    END
  END b[85]
  PIN b[86]
    DIRECTION OUTPUT ;
    USE SIGNAL ;
    PORT
      LAYER M4 ;
        RECT  0 19.344 0.084 19.368 ;
    END
  END b[86]
  PIN b[87]
    DIRECTION OUTPUT ;
    USE SIGNAL ;
    PORT
      LAYER M4 ;
        RECT  0 19.44 0.084 19.464 ;
    END
  END b[87]
  PIN b[88]
    DIRECTION OUTPUT ;
    USE SIGNAL ;
    PORT
      LAYER M4 ;
        RECT  0 19.536 0.084 19.56 ;
    END
  END b[88]
  PIN b[89]
    DIRECTION OUTPUT ;
    USE SIGNAL ;
    PORT
      LAYER M4 ;
        RECT  0 19.632 0.084 19.656 ;
    END
  END b[89]
  PIN b[8]
    DIRECTION OUTPUT ;
    USE SIGNAL ;
    PORT
      LAYER M4 ;
        RECT  0 8.016 0.084 8.04 ;
    END
  END b[8]
  PIN b[90]
    DIRECTION OUTPUT ;
    USE SIGNAL ;
    PORT
      LAYER M4 ;
        RECT  0 19.728 0.084 19.752 ;
    END
  END b[90]
  PIN b[91]
    DIRECTION OUTPUT ;
    USE SIGNAL ;
    PORT
      LAYER M4 ;
        RECT  0 19.824 0.084 19.848 ;
    END
  END b[91]
  PIN b[92]
    DIRECTION OUTPUT ;
    USE SIGNAL ;
    PORT
      LAYER M4 ;
        RECT  0 19.92 0.084 19.944 ;
    END
  END b[92]
  PIN b[93]
    DIRECTION OUTPUT ;
    USE SIGNAL ;
    PORT
      LAYER M4 ;
        RECT  0 20.016 0.084 20.04 ;
    END
  END b[93]
  PIN b[94]
    DIRECTION OUTPUT ;
    USE SIGNAL ;
    PORT
      LAYER M4 ;
        RECT  0 20.112 0.084 20.136 ;
    END
  END b[94]
  PIN b[95]
    DIRECTION OUTPUT ;
    USE SIGNAL ;
    PORT
      LAYER M4 ;
        RECT  0 20.208 0.084 20.232 ;
    END
  END b[95]
  PIN b[96]
    DIRECTION OUTPUT ;
    USE SIGNAL ;
    PORT
      LAYER M4 ;
        RECT  0 20.304 0.084 20.328 ;
    END
  END b[96]
  PIN b[97]
    DIRECTION OUTPUT ;
    USE SIGNAL ;
    PORT
      LAYER M4 ;
        RECT  0 20.4 0.084 20.424 ;
    END
  END b[97]
  PIN b[98]
    DIRECTION OUTPUT ;
    USE SIGNAL ;
    PORT
      LAYER M4 ;
        RECT  0 20.496 0.084 20.52 ;
    END
  END b[98]
  PIN b[99]
    DIRECTION OUTPUT ;
    USE SIGNAL ;
    PORT
      LAYER M4 ;
        RECT  0 20.592 0.084 20.616 ;
    END
  END b[99]
  PIN b[9]
    DIRECTION OUTPUT ;
    USE SIGNAL ;
    PORT
      LAYER M4 ;
        RECT  0 8.112 0.084 8.136 ;
    END
  END b[9]
  PIN ck
    DIRECTION INPUT ;
    USE SIGNAL ;
    PORT
      LAYER M3 ;
        RECT  13.86 30.179 13.878 30.216 ;
    END
  END ck
  PIN ck_s
    DIRECTION INPUT ;
    USE SIGNAL ;
    PORT
      LAYER M3 ;
        RECT  13.932 30.179 13.95 30.216 ;
    END
  END ck_s
  PIN en
    DIRECTION INPUT ;
    USE SIGNAL ;
    PORT
      LAYER M3 ;
        RECT  14.004 30.179 14.022 30.216 ;
    END
  END en
  PIN fault
    DIRECTION OUTPUT ;
    USE SIGNAL ;
    PORT
      LAYER M3 ;
        RECT  14.076 30.179 14.094 30.216 ;
    END
  END fault
  PIN k0
    DIRECTION INPUT ;
    USE SIGNAL ;
    PORT
      LAYER M3 ;
        RECT  14.148 30.179 14.166 30.216 ;
    END
  END k0
  PIN k1
    DIRECTION INPUT ;
    USE SIGNAL ;
    PORT
      LAYER M3 ;
        RECT  14.22 30.179 14.238 30.216 ;
    END
  END k1
  PIN k2
    DIRECTION INPUT ;
    USE SIGNAL ;
    PORT
      LAYER M3 ;
        RECT  14.292 30.179 14.31 30.216 ;
    END
  END k2
  PIN rs
    DIRECTION INPUT ;
    USE SIGNAL ;
    PORT
      LAYER M3 ;
        RECT  14.364 30.179 14.382 30.216 ;
    END
  END rs
  PIN tie_hi
    DIRECTION OUTPUT ;
    USE SIGNAL ;
    PORT
      LAYER M3 ;
        RECT  14.436 30.179 14.454 30.216 ;
    END
  END tie_hi
  PIN tie_lo
    DIRECTION OUTPUT ;
    USE SIGNAL ;
    PORT
      LAYER M3 ;
        RECT  14.508 30.179 14.526 30.216 ;
    END
  END tie_lo
  PIN VDD
    DIRECTION INOUT ;
    USE POWER ;
    PORT
      LAYER M5 ;
        RECT  61.992 2.151 62.112 27.833 ;
        RECT  59.292 2.151 59.412 27.833 ;
        RECT  56.592 2.151 56.712 27.833 ;
        RECT  53.892 2.151 54.012 27.833 ;
        RECT  51.192 2.151 51.312 27.833 ;
        RECT  48.492 2.151 48.612 27.833 ;
        RECT  45.792 2.151 45.912 27.833 ;
        RECT  43.092 2.151 43.212 27.833 ;
        RECT  40.392 2.151 40.512 27.833 ;
        RECT  37.692 2.151 37.812 27.833 ;
        RECT  34.992 2.151 35.112 27.833 ;
        RECT  32.292 2.151 32.412 27.833 ;
        RECT  29.592 2.151 29.712 27.833 ;
        RECT  26.892 2.151 27.012 27.833 ;
        RECT  24.192 2.151 24.312 27.833 ;
        RECT  21.492 2.151 21.612 27.833 ;
        RECT  18.792 2.151 18.912 27.833 ;
        RECT  16.092 2.151 16.212 27.833 ;
        RECT  13.392 2.151 13.512 27.833 ;
        RECT  10.692 2.151 10.812 27.833 ;
        RECT  7.992 2.151 8.112 27.833 ;
        RECT  5.292 2.151 5.412 27.833 ;
        RECT  2.592 2.151 2.712 27.833 ;
    END
  END VDD
  PIN VSS
    DIRECTION INOUT ;
    USE GROUND ;
    PORT
      LAYER M5 ;
        RECT  61.8 2.137 61.92 27.819 ;
        RECT  59.1 2.137 59.22 27.819 ;
        RECT  56.4 2.137 56.52 27.819 ;
        RECT  53.7 2.137 53.82 27.819 ;
        RECT  51 2.137 51.12 27.819 ;
        RECT  48.3 2.137 48.42 27.819 ;
        RECT  45.6 2.137 45.72 27.819 ;
        RECT  42.9 2.137 43.02 27.819 ;
        RECT  40.2 2.137 40.32 27.819 ;
        RECT  37.5 2.137 37.62 27.819 ;
        RECT  34.8 2.137 34.92 27.819 ;
        RECT  32.1 2.137 32.22 27.819 ;
        RECT  29.4 2.137 29.52 27.819 ;
        RECT  26.7 2.137 26.82 27.819 ;
        RECT  24 2.137 24.12 27.819 ;
        RECT  21.3 2.137 21.42 27.819 ;
        RECT  18.6 2.137 18.72 27.819 ;
        RECT  15.9 2.137 16.02 27.819 ;
        RECT  13.2 2.137 13.32 27.819 ;
        RECT  10.5 2.137 10.62 27.819 ;
        RECT  7.8 2.137 7.92 27.819 ;
        RECT  5.1 2.137 5.22 27.819 ;
        RECT  2.4 2.137 2.52 27.819 ;
    END
  END VSS
  OBS
    LAYER RVTN ;
     RECT  2.16 2.16 62.586 2.295 ;
     RECT  2.16 2.565 62.586 2.835 ;
     RECT  2.16 3.105 62.586 3.375 ;
     RECT  2.16 3.645 62.586 3.915 ;
     RECT  2.16 4.185 62.586 4.455 ;
     RECT  2.16 4.725 62.586 4.995 ;
     RECT  2.16 5.265 62.586 5.535 ;
     RECT  2.16 5.805 62.586 6.075 ;
     RECT  2.16 6.345 62.586 6.615 ;
     RECT  2.16 6.885 62.586 7.155 ;
     RECT  2.16 7.425 62.586 7.695 ;
     RECT  2.16 7.965 62.586 8.235 ;
     RECT  2.16 8.505 62.586 8.775 ;
     RECT  2.16 9.045 62.586 9.315 ;
     RECT  2.16 9.585 62.586 9.855 ;
     RECT  2.16 10.125 62.586 10.395 ;
     RECT  2.16 10.665 62.586 10.935 ;
     RECT  2.16 11.205 62.586 11.475 ;
     RECT  2.16 11.745 62.586 12.015 ;
     RECT  2.16 12.285 62.586 12.555 ;
     RECT  2.16 12.825 62.586 13.095 ;
     RECT  2.16 13.365 62.586 13.635 ;
     RECT  2.16 13.905 62.586 14.175 ;
     RECT  2.16 14.445 62.586 14.715 ;
     RECT  2.16 14.985 62.586 15.255 ;
     RECT  2.16 15.525 62.586 15.795 ;
     RECT  2.16 16.065 62.586 16.335 ;
     RECT  2.16 16.605 62.586 16.875 ;
     RECT  2.16 17.145 62.586 17.415 ;
     RECT  2.16 17.685 62.586 17.955 ;
     RECT  2.16 18.225 62.586 18.495 ;
     RECT  2.16 18.765 62.586 19.035 ;
     RECT  2.16 19.305 62.586 19.575 ;
     RECT  2.16 19.845 62.586 20.115 ;
     RECT  2.16 20.385 62.586 20.655 ;
     RECT  2.16 20.925 62.586 21.195 ;
     RECT  2.16 21.465 62.586 21.735 ;
     RECT  2.16 22.005 62.586 22.275 ;
     RECT  2.16 22.545 62.586 22.815 ;
     RECT  2.16 23.085 62.586 23.355 ;
     RECT  2.16 23.625 62.586 23.895 ;
     RECT  2.16 24.165 62.586 24.435 ;
     RECT  2.16 24.705 62.586 24.975 ;
     RECT  2.16 25.245 62.586 25.515 ;
     RECT  2.16 25.785 62.586 26.055 ;
     RECT  2.16 26.325 62.586 26.595 ;
     RECT  2.16 26.865 62.586 27.135 ;
     RECT  2.16 27.405 62.586 27.675 ;
    LAYER RVTP ;
     RECT  2.16 2.295 62.586 2.565 ;
     RECT  2.16 2.835 62.586 3.105 ;
     RECT  2.16 3.375 62.586 3.645 ;
     RECT  2.16 3.915 62.586 4.185 ;
     RECT  2.16 4.455 62.586 4.725 ;
     RECT  2.16 4.995 62.586 5.265 ;
     RECT  2.16 5.535 62.586 5.805 ;
     RECT  2.16 6.075 62.586 6.345 ;
     RECT  2.16 6.615 62.586 6.885 ;
     RECT  2.16 7.155 62.586 7.425 ;
     RECT  2.16 7.695 62.586 7.965 ;
     RECT  2.16 8.235 62.586 8.505 ;
     RECT  2.16 8.775 62.586 9.045 ;
     RECT  2.16 9.315 62.586 9.585 ;
     RECT  2.16 9.855 62.586 10.125 ;
     RECT  2.16 10.395 62.586 10.665 ;
     RECT  2.16 10.935 62.586 11.205 ;
     RECT  2.16 11.475 62.586 11.745 ;
     RECT  2.16 12.015 62.586 12.285 ;
     RECT  2.16 12.555 62.586 12.825 ;
     RECT  2.16 13.095 62.586 13.365 ;
     RECT  2.16 13.635 62.586 13.905 ;
     RECT  2.16 14.175 62.586 14.445 ;
     RECT  2.16 14.715 62.586 14.985 ;
     RECT  2.16 15.255 62.586 15.525 ;
     RECT  2.16 15.795 62.586 16.065 ;
     RECT  2.16 16.335 62.586 16.605 ;
     RECT  2.16 16.875 62.586 17.145 ;
     RECT  2.16 17.415 62.586 17.685 ;
     RECT  2.16 17.955 62.586 18.225 ;
     RECT  2.16 18.495 62.586 18.765 ;
     RECT  2.16 19.035 62.586 19.305 ;
     RECT  2.16 19.575 62.586 19.845 ;
     RECT  2.16 20.115 62.586 20.385 ;
     RECT  2.16 20.655 62.586 20.925 ;
     RECT  2.16 21.195 62.586 21.465 ;
     RECT  2.16 21.735 62.586 22.005 ;
     RECT  2.16 22.275 62.586 22.545 ;
     RECT  2.16 22.815 62.586 23.085 ;
     RECT  2.16 23.355 62.586 23.625 ;
     RECT  2.16 23.895 62.586 24.165 ;
     RECT  2.16 24.435 62.586 24.705 ;
     RECT  2.16 24.975 62.586 25.245 ;
     RECT  2.16 25.515 62.586 25.785 ;
     RECT  2.16 26.055 62.586 26.325 ;
     RECT  2.16 26.595 62.586 26.865 ;
     RECT  2.16 27.135 62.586 27.405 ;
     RECT  2.16 27.675 62.586 27.81 ;
    LAYER M1 ;
     RECT  2.16 2.151 62.586 27.819 ;
    LAYER M2 ;
     RECT  0.103 6.012 0.139 6.714 ;
     RECT  0.103 16.956 0.139 16.974 ;
     RECT  0.103 21.591 0.139 21.609 ;
     RECT  0.103 22.518 0.139 23.274 ;
     RECT  0.139 16.956 0.175 17.064 ;
     RECT  0.139 21.591 0.203 23.274 ;
     RECT  0.139 6.012 0.211 6.804 ;
     RECT  0.139 8.136 0.239 8.154 ;
     RECT  0.203 23.256 0.239 23.274 ;
     RECT  0.211 6.012 0.247 7.38 ;
     RECT  0.203 21.78 0.275 21.798 ;
     RECT  0.247 5.616 0.311 7.38 ;
     RECT  0.103 8.982 0.347 9 ;
     RECT  0.175 16.506 0.427 17.064 ;
     RECT  0.463 3.654 0.499 3.672 ;
     RECT  0.499 3.186 0.535 3.672 ;
     RECT  0.175 4.806 0.535 4.824 ;
     RECT  0.311 5.616 0.535 6.804 ;
     RECT  0.427 16.506 0.535 17.514 ;
     RECT  0.535 3.186 2.16 3.978 ;
     RECT  0.535 4.806 2.16 6.804 ;
     RECT  0.535 16.506 2.16 18.792 ;
     RECT  13.783 30.114 13.955 30.132 ;
     RECT  2.16 2.151 14.395 27.819 ;
     RECT  14.395 2.151 14.531 27.864 ;
     RECT  14.531 2.151 18.139 27.819 ;
     RECT  18.139 2.151 20.327 27.864 ;
     RECT  20.327 2.151 62.586 27.819 ;
     RECT  62.586 6.318 62.771 13.086 ;
     RECT  62.586 18.198 62.771 27.738 ;
     RECT  62.771 6.318 62.843 6.876 ;
     RECT  62.771 18.198 62.987 25.308 ;
     RECT  62.987 18.774 63.023 25.308 ;
     RECT  62.771 26.1 63.059 27.738 ;
     RECT  63.059 26.1 63.275 27.234 ;
     RECT  62.843 6.318 63.311 6.408 ;
     RECT  62.771 7.632 63.311 13.086 ;
     RECT  63.023 19.08 63.311 25.308 ;
     RECT  63.275 26.1 63.311 26.964 ;
     RECT  63.311 19.08 63.347 24.768 ;
     RECT  63.311 26.1 63.347 26.118 ;
     RECT  63.347 19.548 63.383 24.768 ;
     RECT  63.383 24.75 63.491 24.768 ;
     RECT  63.383 19.548 63.779 23.886 ;
     RECT  63.311 10.674 63.851 12.852 ;
     RECT  63.779 19.548 63.851 23.346 ;
     RECT  63.311 26.946 63.851 26.964 ;
     RECT  63.311 6.39 63.887 6.408 ;
     RECT  63.311 7.632 63.887 9.846 ;
     RECT  63.851 10.674 63.887 12.816 ;
     RECT  63.851 19.548 63.887 22.77 ;
     RECT  63.887 7.632 63.923 8.73 ;
     RECT  63.887 10.908 63.923 11.268 ;
     RECT  63.887 12.6 63.923 12.618 ;
     RECT  63.887 20.934 63.923 22.77 ;
     RECT  63.887 20.052 63.959 20.07 ;
     RECT  63.923 22.356 63.959 22.374 ;
     RECT  63.923 8.046 63.995 8.73 ;
     RECT  63.923 10.908 63.995 11.232 ;
     RECT  63.923 20.934 63.995 20.952 ;
     RECT  63.995 10.908 64.031 10.926 ;
     RECT  64.651 7.236 64.751 7.92 ;
     RECT  64.651 8.856 64.751 10.224 ;
    LAYER M3 ;
     RECT  7.815 2.143 7.905 2.227 ;
     RECT  7.815 2.227 9.018 2.263 ;
     RECT  7.815 2.263 9.522 2.299 ;
     RECT  10.515 2.143 10.605 2.299 ;
     RECT  32.115 2.143 32.205 2.299 ;
     RECT  34.815 2.143 34.905 2.299 ;
     RECT  13.215 2.143 13.305 2.335 ;
     RECT  16.956 2.299 16.974 2.335 ;
     RECT  17.82 2.191 17.838 2.335 ;
     RECT  7.815 2.299 10.605 2.371 ;
     RECT  15.915 2.143 16.005 2.371 ;
     RECT  19.584 2.335 19.602 2.371 ;
     RECT  30.78 2.335 30.798 2.371 ;
     RECT  31.536 2.299 32.205 2.371 ;
     RECT  33.48 2.335 33.498 2.371 ;
     RECT  2.415 2.143 2.505 2.413 ;
     RECT  5.115 2.143 5.205 2.413 ;
     RECT  7.164 2.371 10.605 2.413 ;
     RECT  11.412 2.299 11.43 2.413 ;
     RECT  13.104 2.335 13.305 2.413 ;
     RECT  14.112 2.299 14.13 2.413 ;
     RECT  15.624 2.371 16.005 2.413 ;
     RECT  18.615 2.143 18.705 2.413 ;
     RECT  19.584 2.371 19.674 2.413 ;
     RECT  21.315 2.143 21.405 2.413 ;
     RECT  24.015 2.143 24.105 2.413 ;
     RECT  26.715 2.143 26.805 2.413 ;
     RECT  29.415 2.143 29.505 2.413 ;
     RECT  30.276 2.371 30.798 2.413 ;
     RECT  34.56 2.299 34.905 2.413 ;
     RECT  37.515 2.143 37.605 2.413 ;
     RECT  40.215 2.143 40.305 2.413 ;
     RECT  42.915 2.143 43.005 2.413 ;
     RECT  45.615 2.143 45.705 2.413 ;
     RECT  48.315 2.143 48.405 2.413 ;
     RECT  51.015 2.143 51.105 2.413 ;
     RECT  53.715 2.143 53.805 2.413 ;
     RECT  56.415 2.143 56.505 2.413 ;
     RECT  59.115 2.143 59.205 2.413 ;
     RECT  61.815 2.143 61.905 2.413 ;
     RECT  16.956 2.335 17.838 2.461 ;
     RECT  18.615 2.413 19.674 2.461 ;
     RECT  24.015 2.413 24.297 2.461 ;
     RECT  29.415 2.413 30.798 2.461 ;
     RECT  26.715 2.413 26.997 2.488 ;
     RECT  31.536 2.371 33.498 2.497 ;
     RECT  34.56 2.413 35.097 2.497 ;
     RECT  23.328 2.461 24.297 2.569 ;
     RECT  29.16 2.461 30.798 2.569 ;
     RECT  31.536 2.497 35.097 2.569 ;
     RECT  13.104 2.413 14.13 2.587 ;
     RECT  7.164 2.413 11.43 2.605 ;
     RECT  13.104 2.587 14.634 2.605 ;
     RECT  29.16 2.569 35.097 2.605 ;
     RECT  7.164 2.605 11.61 2.641 ;
     RECT  13.104 2.605 14.814 2.641 ;
     RECT  15.624 2.413 16.197 2.641 ;
     RECT  22.968 2.569 24.297 2.641 ;
     RECT  25.2 2.491 25.326 2.641 ;
     RECT  26.715 2.488 27.09 2.641 ;
     RECT  2.415 2.413 2.697 2.731 ;
     RECT  3.492 2.641 3.51 2.731 ;
     RECT  4.32 2.641 4.338 2.731 ;
     RECT  5.115 2.413 5.397 2.731 ;
     RECT  6.264 2.711 6.282 2.731 ;
     RECT  12.888 2.641 14.814 2.731 ;
     RECT  15.588 2.641 16.197 2.731 ;
     RECT  16.956 2.461 19.674 2.731 ;
     RECT  22.932 2.641 24.297 2.731 ;
     RECT  7.164 2.641 12.042 2.767 ;
     RECT  12.888 2.731 16.197 2.767 ;
     RECT  28.656 2.605 35.097 2.767 ;
     RECT  21.315 2.413 21.597 2.839 ;
     RECT  28.62 2.767 35.097 2.839 ;
     RECT  22.932 2.731 24.462 2.875 ;
     RECT  25.2 2.641 27.702 2.875 ;
     RECT  28.548 2.839 35.097 2.875 ;
     RECT  2.415 2.731 3.51 2.911 ;
     RECT  4.248 2.731 6.282 2.911 ;
     RECT  21.315 2.839 22.05 2.911 ;
     RECT  22.932 2.875 35.097 2.911 ;
     RECT  2.415 2.911 6.282 3.067 ;
     RECT  7.164 2.767 16.197 3.067 ;
     RECT  21.315 2.911 35.097 3.163 ;
     RECT  21.204 3.163 35.097 3.181 ;
     RECT  2.415 3.067 16.197 3.271 ;
     RECT  16.956 2.731 20.034 3.271 ;
     RECT  2.415 3.271 20.034 3.335 ;
     RECT  48.315 2.413 48.597 3.343 ;
     RECT  42.915 2.413 43.197 3.355 ;
     RECT  21.132 3.181 35.262 3.407 ;
     RECT  2.415 3.335 14.634 3.451 ;
     RECT  21.132 3.407 27.126 3.451 ;
     RECT  27.9 3.407 35.262 3.569 ;
     RECT  15.588 3.335 20.034 3.577 ;
     RECT  15.588 3.577 20.142 3.595 ;
     RECT  21.06 3.451 27.126 3.595 ;
     RECT  0.504 3.181 0.522 3.649 ;
     RECT  2.376 3.451 14.634 3.677 ;
     RECT  2.376 3.677 14.382 3.685 ;
     RECT  40.215 2.413 40.497 3.685 ;
     RECT  0.468 3.649 1.17 3.749 ;
     RECT  28.26 3.569 35.262 3.835 ;
     RECT  28.26 3.835 35.442 3.839 ;
     RECT  28.26 3.839 31.374 3.875 ;
     RECT  32.115 3.839 35.442 3.883 ;
     RECT  42.915 3.355 43.578 3.919 ;
     RECT  32.115 3.883 35.982 3.947 ;
     RECT  15.588 3.595 27.126 4.117 ;
     RECT  15.264 4.117 27.126 4.157 ;
     RECT  45.615 2.413 45.897 4.189 ;
     RECT  46.656 3.451 46.674 4.189 ;
     RECT  0.468 3.749 0.558 4.205 ;
     RECT  42.192 3.919 43.578 4.261 ;
     RECT  0.468 4.205 0.522 4.301 ;
     RECT  15.696 4.157 27.126 4.379 ;
     RECT  15.768 4.379 27.126 4.451 ;
     RECT  18.396 4.451 27.126 4.459 ;
     RECT  2.304 3.685 14.382 4.495 ;
     RECT  18.396 4.459 27.234 4.495 ;
     RECT  28.26 3.875 30.942 4.495 ;
     RECT  2.304 4.495 14.49 4.621 ;
     RECT  18.396 4.495 30.942 4.657 ;
     RECT  32.115 3.947 35.91 4.657 ;
     RECT  0.468 4.301 0.486 4.699 ;
     RECT  41.724 4.261 43.578 4.729 ;
     RECT  2.304 4.621 14.778 4.891 ;
     RECT  18.396 4.657 35.91 4.891 ;
     RECT  36.72 4.693 36.738 4.891 ;
     RECT  37.515 2.413 37.797 4.891 ;
     RECT  41.724 4.729 43.974 4.919 ;
     RECT  18.396 4.891 37.797 5.027 ;
     RECT  0.144 4.699 0.486 5.071 ;
     RECT  42.915 4.919 43.974 5.189 ;
     RECT  2.304 4.891 14.814 5.233 ;
     RECT  15.768 4.451 17.622 5.233 ;
     RECT  53.715 2.413 53.997 5.233 ;
     RECT  48.168 3.343 48.597 5.305 ;
     RECT  2.304 5.233 17.622 5.341 ;
     RECT  18.396 5.027 30.222 5.341 ;
     RECT  2.304 5.341 30.222 5.357 ;
     RECT  39.348 5.161 39.366 5.539 ;
     RECT  40.215 3.685 40.878 5.539 ;
     RECT  53.715 5.233 54.234 5.575 ;
     RECT  2.415 5.357 30.222 5.603 ;
     RECT  39.348 5.539 40.878 5.729 ;
     RECT  45.615 4.189 46.674 5.729 ;
     RECT  53.676 5.575 54.234 5.737 ;
     RECT  31.14 5.027 37.797 5.755 ;
     RECT  55.44 5.467 55.458 5.773 ;
     RECT  56.415 2.413 56.697 5.773 ;
     RECT  2.415 5.603 30.078 5.801 ;
     RECT  43.956 5.189 43.974 5.809 ;
     RECT  31.068 5.755 37.797 5.845 ;
     RECT  0.144 5.071 0.558 5.899 ;
     RECT  9.288 5.801 30.078 5.999 ;
     RECT  39.348 5.729 40.554 5.999 ;
     RECT  41.724 4.919 41.742 5.999 ;
     RECT  52.992 5.737 54.234 6.007 ;
     RECT  42.915 5.189 43.197 6.043 ;
     RECT  55.44 5.773 56.697 6.043 ;
     RECT  15.624 5.999 30.078 6.107 ;
     RECT  41.688 6.043 41.706 6.115 ;
     RECT  52.776 6.007 54.234 6.115 ;
     RECT  41.616 6.115 41.706 6.143 ;
     RECT  39.348 5.999 40.497 6.179 ;
     RECT  48.024 5.305 48.597 6.179 ;
     RECT  39.348 6.179 39.366 6.269 ;
     RECT  55.404 6.043 56.697 6.277 ;
     RECT  42.66 6.043 43.197 6.331 ;
     RECT  43.956 5.809 44.442 6.331 ;
     RECT  63.288 6.313 63.306 6.385 ;
     RECT  9.288 5.999 14.886 6.413 ;
     RECT  41.616 6.143 41.634 6.449 ;
     RECT  0.108 5.899 0.558 6.509 ;
     RECT  15.696 6.107 30.078 6.511 ;
     RECT  30.816 5.845 37.797 6.511 ;
     RECT  51.015 2.413 51.297 6.511 ;
     RECT  38.88 6.421 38.898 6.539 ;
     RECT  55.332 6.277 56.697 6.539 ;
     RECT  2.415 5.801 8.55 6.583 ;
     RECT  9.288 6.413 11.25 6.583 ;
     RECT  2.376 6.583 11.25 6.647 ;
     RECT  15.696 6.511 37.854 6.647 ;
     RECT  50.724 6.511 51.297 6.647 ;
     RECT  34.2 6.647 37.854 6.655 ;
     RECT  59.115 2.413 59.397 6.655 ;
     RECT  60.192 6.283 60.21 6.655 ;
     RECT  34.2 6.655 37.962 6.691 ;
     RECT  52.704 6.115 54.234 6.691 ;
     RECT  55.332 6.539 55.674 6.691 ;
     RECT  9.936 6.647 11.25 6.719 ;
     RECT  34.2 6.691 38.106 6.719 ;
     RECT  2.376 6.647 8.694 6.809 ;
     RECT  37.515 6.719 38.106 6.809 ;
     RECT  42.66 6.331 44.442 6.809 ;
     RECT  61.815 2.413 62.097 6.817 ;
     RECT  63.288 6.385 63.882 6.817 ;
     RECT  2.376 6.809 8.658 6.845 ;
     RECT  2.376 6.845 8.55 6.853 ;
     RECT  11.988 6.413 14.886 6.853 ;
     RECT  15.696 6.647 33.282 6.853 ;
     RECT  59.115 6.655 60.21 6.893 ;
     RECT  52.704 6.691 55.674 6.941 ;
     RECT  61.815 6.817 63.882 6.989 ;
     RECT  34.2 6.719 36.738 7.079 ;
     RECT  63.864 6.989 63.882 7.085 ;
     RECT  60.228 6.907 60.462 7.133 ;
     RECT  1.152 6.955 1.278 7.181 ;
     RECT  10.08 6.719 11.25 7.195 ;
     RECT  11.988 6.853 33.282 7.195 ;
     RECT  52.704 6.941 55.35 7.195 ;
     RECT  52.56 7.195 55.35 7.229 ;
     RECT  64.728 7.195 64.746 7.231 ;
     RECT  45.615 5.729 46.242 7.259 ;
     RECT  0.108 6.509 0.162 7.339 ;
     RECT  42.66 6.809 44.334 7.349 ;
     RECT  58.14 6.691 58.158 7.349 ;
     RECT  0.108 7.339 0.234 7.357 ;
     RECT  45.615 7.259 45.897 7.387 ;
     RECT  42.66 7.349 44.082 7.393 ;
     RECT  52.56 7.229 54.846 7.469 ;
     RECT  10.08 7.195 33.282 7.501 ;
     RECT  2.304 6.853 8.55 7.579 ;
     RECT  9.648 7.501 33.282 7.579 ;
     RECT  40.215 6.179 40.497 7.591 ;
     RECT  42.516 7.393 44.082 7.619 ;
     RECT  34.2 7.079 36.63 7.627 ;
     RECT  41.724 7.231 41.742 7.663 ;
     RECT  48.315 6.179 48.597 7.699 ;
     RECT  51.015 6.647 51.297 7.699 ;
     RECT  59.115 6.893 59.397 7.699 ;
     RECT  52.56 7.469 52.578 7.709 ;
     RECT  41.292 7.663 41.742 7.735 ;
     RECT  42.516 7.619 43.326 7.735 ;
     RECT  47.304 7.051 47.322 7.735 ;
     RECT  48.096 7.699 48.597 7.735 ;
     RECT  0.108 7.357 0.306 7.757 ;
     RECT  0.144 7.757 0.306 7.819 ;
     RECT  58.716 7.699 59.397 7.861 ;
     RECT  2.304 7.579 33.282 7.889 ;
     RECT  44.064 7.619 44.082 7.889 ;
     RECT  34.128 7.627 36.63 7.897 ;
     RECT  37.515 6.809 37.89 7.897 ;
     RECT  38.664 6.889 38.79 7.897 ;
     RECT  41.292 7.735 43.326 7.925 ;
     RECT  64.656 7.231 64.746 7.925 ;
     RECT  61.815 6.989 62.91 7.933 ;
     RECT  63.9 7.627 63.918 7.933 ;
     RECT  0.144 7.819 0.342 7.949 ;
     RECT  58.716 7.861 59.634 7.949 ;
     RECT  64.656 7.925 64.674 7.949 ;
     RECT  39.78 7.591 40.497 7.969 ;
     RECT  58.716 7.949 59.49 7.997 ;
     RECT  34.128 7.897 38.79 8.005 ;
     RECT  9.972 7.889 33.282 8.041 ;
     RECT  34.128 8.005 38.898 8.041 ;
     RECT  61.815 7.933 63.918 8.041 ;
     RECT  60.444 7.133 60.462 8.045 ;
     RECT  42.516 7.925 43.197 8.069 ;
     RECT  61.815 8.041 63.99 8.141 ;
     RECT  50.724 7.699 51.297 8.167 ;
     RECT  2.304 7.889 9.126 8.195 ;
     RECT  9.972 8.041 38.898 8.231 ;
     RECT  39.672 7.969 40.497 8.303 ;
     RECT  56.415 6.539 56.697 8.311 ;
     RECT  15.915 8.231 38.898 8.429 ;
     RECT  47.304 7.735 48.597 8.429 ;
     RECT  53.424 7.469 54.846 8.437 ;
     RECT  9.972 8.231 15.174 8.465 ;
     RECT  53.424 8.437 55.278 8.473 ;
     RECT  56.088 8.311 56.697 8.473 ;
     RECT  53.424 8.473 56.697 8.509 ;
     RECT  50.688 8.167 51.297 8.581 ;
     RECT  36.9 8.429 38.79 8.609 ;
     RECT  36.972 8.609 38.79 8.699 ;
     RECT  41.292 7.925 41.31 8.699 ;
     RECT  52.956 8.509 56.697 8.699 ;
     RECT  37.044 8.699 38.79 8.735 ;
     RECT  50.04 8.581 51.297 8.735 ;
     RECT  52.992 8.699 56.697 8.743 ;
     RECT  58.716 7.997 59.397 8.807 ;
     RECT  45.36 7.387 45.897 8.815 ;
     RECT  60.624 8.581 60.642 8.827 ;
     RECT  40.215 8.303 40.497 8.851 ;
     RECT  63.288 8.141 63.99 8.851 ;
     RECT  64.728 8.827 64.746 8.851 ;
     RECT  9.972 8.465 15.066 8.941 ;
     RECT  60.624 8.827 60.966 8.941 ;
     RECT  0.144 7.949 0.234 8.968 ;
     RECT  40.215 8.851 41.202 8.969 ;
     RECT  46.764 8.671 47.034 8.969 ;
     RECT  57.816 8.815 57.834 8.969 ;
     RECT  58.788 8.807 59.397 8.969 ;
     RECT  0.108 8.968 0.234 8.977 ;
     RECT  0.108 8.977 0.342 9.005 ;
     RECT  52.992 8.743 57.006 9.005 ;
     RECT  42.66 8.069 43.197 9.019 ;
     RECT  61.815 8.141 62.097 9.067 ;
     RECT  63.288 8.851 64.746 9.067 ;
     RECT  60.444 8.941 60.966 9.077 ;
     RECT  59.115 8.969 59.397 9.085 ;
     RECT  60.444 9.077 60.462 9.085 ;
     RECT  53.715 9.005 56.697 9.113 ;
     RECT  45.216 8.815 45.897 9.149 ;
     RECT  9.108 8.195 9.126 9.163 ;
     RECT  9.936 8.941 15.066 9.163 ;
     RECT  2.304 8.195 8.37 9.205 ;
     RECT  9.108 9.163 15.066 9.205 ;
     RECT  2.304 9.205 15.066 9.211 ;
     RECT  15.915 8.429 36.018 9.211 ;
     RECT  47.88 8.429 48.597 9.239 ;
     RECT  42.66 9.019 43.65 9.259 ;
     RECT  59.115 9.085 60.462 9.293 ;
     RECT  61.815 9.067 64.746 9.389 ;
     RECT  2.304 9.211 36.018 9.481 ;
     RECT  40.215 8.969 40.734 9.509 ;
     RECT  46.908 8.969 46.926 9.509 ;
     RECT  54.792 9.113 56.697 9.509 ;
     RECT  2.304 9.481 36.306 9.581 ;
     RECT  37.188 8.735 38.79 9.625 ;
     RECT  42.48 9.259 43.65 9.625 ;
     RECT  2.304 9.581 25.434 9.643 ;
     RECT  2.268 9.643 25.434 9.689 ;
     RECT  26.208 9.581 36.306 9.751 ;
     RECT  26.208 9.751 36.414 9.781 ;
     RECT  48.315 9.239 48.597 9.787 ;
     RECT  59.115 9.293 60.426 9.821 ;
     RECT  0.324 9.005 0.342 9.869 ;
     RECT  59.115 9.821 59.397 9.883 ;
     RECT  40.215 9.509 40.497 9.895 ;
     RECT  26.208 9.781 36.45 9.925 ;
     RECT  37.188 9.625 38.862 9.925 ;
     RECT  26.208 9.925 38.862 9.931 ;
     RECT  39.744 9.895 40.497 9.931 ;
     RECT  2.304 9.689 25.434 10.049 ;
     RECT  26.208 9.931 40.497 10.049 ;
     RECT  42.192 9.625 43.65 10.049 ;
     RECT  48.315 9.787 48.654 10.049 ;
     RECT  20.7 10.049 25.434 10.085 ;
     RECT  48.315 10.049 48.597 10.093 ;
     RECT  53.715 9.113 53.997 10.093 ;
     RECT  54.792 9.509 55.026 10.093 ;
     RECT  45.36 9.149 45.897 10.129 ;
     RECT  58.716 9.883 59.397 10.157 ;
     RECT  60.3 9.821 60.426 10.193 ;
     RECT  64.656 9.389 64.746 10.229 ;
     RECT  0.216 9.883 0.234 10.253 ;
     RECT  64.656 10.229 64.674 10.253 ;
     RECT  53.715 10.093 55.026 10.291 ;
     RECT  55.764 9.509 56.697 10.291 ;
     RECT  45.252 10.129 45.897 10.319 ;
     RECT  48.276 10.093 48.597 10.319 ;
     RECT  20.772 10.085 25.398 10.355 ;
     RECT  61.815 9.389 63.882 10.355 ;
     RECT  52.416 10.123 52.434 10.399 ;
     RECT  61.815 10.355 62.766 10.471 ;
     RECT  39.348 10.049 40.497 10.499 ;
     RECT  52.308 10.399 52.434 10.589 ;
     RECT  63.864 10.355 63.882 10.603 ;
     RECT  45.615 10.319 45.897 10.633 ;
     RECT  61.524 10.471 62.766 10.637 ;
     RECT  60.336 10.193 60.426 10.651 ;
     RECT  53.715 10.291 56.697 10.685 ;
     RECT  42.804 10.049 43.197 10.697 ;
     RECT  39.348 10.499 39.366 10.769 ;
     RECT  60.336 10.651 60.498 10.769 ;
     RECT  57.564 10.633 57.582 10.859 ;
     RECT  59.115 10.157 59.397 10.891 ;
     RECT  59.115 10.891 59.49 10.903 ;
     RECT  63.864 10.603 64.026 10.931 ;
     RECT  2.304 10.049 19.926 10.939 ;
     RECT  20.772 10.355 22.194 10.939 ;
     RECT  42.915 10.697 43.197 10.939 ;
     RECT  59.076 10.903 59.49 10.939 ;
     RECT  59.076 10.939 60.174 10.975 ;
     RECT  22.968 10.355 25.398 11.011 ;
     RECT  26.208 10.049 38.07 11.011 ;
     RECT  59.004 10.975 60.174 11.011 ;
     RECT  49.392 10.987 49.41 11.039 ;
     RECT  52.668 10.867 52.758 11.039 ;
     RECT  50.724 8.735 51.297 11.101 ;
     RECT  2.304 10.939 22.194 11.137 ;
     RECT  22.968 11.011 38.214 11.137 ;
     RECT  48.315 10.319 48.597 11.137 ;
     RECT  58.608 11.011 60.174 11.165 ;
     RECT  61.524 10.637 62.694 11.165 ;
     RECT  2.304 11.137 38.214 11.179 ;
     RECT  50.652 11.101 51.297 11.201 ;
     RECT  50.724 11.201 51.297 11.227 ;
     RECT  47.7 11.137 48.597 11.237 ;
     RECT  59.004 11.165 60.174 11.237 ;
     RECT  63.864 10.931 63.99 11.237 ;
     RECT  63.864 11.237 63.918 11.273 ;
     RECT  45.615 10.633 46.026 11.281 ;
     RECT  2.304 11.179 38.79 11.309 ;
     RECT  60.948 11.272 60.966 11.309 ;
     RECT  40.215 10.499 40.497 11.371 ;
     RECT  41.544 10.633 41.634 11.371 ;
     RECT  2.304 11.309 38.682 11.399 ;
     RECT  59.04 11.237 60.174 11.399 ;
     RECT  42.915 10.939 43.65 11.407 ;
     RECT  53.715 10.685 55.35 11.407 ;
     RECT  40.215 11.371 41.634 11.467 ;
     RECT  61.815 11.165 62.694 11.467 ;
     RECT  3.6 11.399 3.942 11.471 ;
     RECT  56.415 10.685 56.697 11.479 ;
     RECT  53.388 11.407 55.35 11.501 ;
     RECT  50.724 11.227 51.57 11.515 ;
     RECT  3.6 11.471 3.87 11.543 ;
     RECT  42.915 11.407 43.794 11.543 ;
     RECT  45.072 11.281 46.026 11.551 ;
     RECT  56.415 11.479 57.402 11.551 ;
     RECT  61.815 11.467 62.73 11.563 ;
     RECT  42.915 11.543 43.686 11.641 ;
     RECT  45.072 11.551 46.53 11.641 ;
     RECT  61.815 11.563 62.766 11.659 ;
     RECT  2.304 11.399 2.697 11.669 ;
     RECT  45.072 11.641 46.782 11.705 ;
     RECT  4.68 11.399 38.682 11.741 ;
     RECT  42.768 11.641 43.686 11.785 ;
     RECT  55.548 11.551 57.402 11.785 ;
     RECT  53.388 11.501 54.81 11.821 ;
     RECT  55.548 11.785 57.438 11.821 ;
     RECT  55.548 11.821 57.474 11.911 ;
     RECT  50.724 11.515 51.894 11.939 ;
     RECT  53.28 11.821 54.81 11.947 ;
     RECT  18.615 11.741 38.682 11.975 ;
     RECT  40.215 11.467 41.706 11.975 ;
     RECT  49.752 11.479 49.77 11.975 ;
     RECT  50.796 11.939 51.894 11.975 ;
     RECT  42.588 11.785 43.686 11.981 ;
     RECT  55.548 11.911 57.51 12.019 ;
     RECT  55.548 12.019 58.194 12.047 ;
     RECT  53.172 11.947 54.81 12.077 ;
     RECT  61.815 11.659 62.838 12.139 ;
     RECT  63.864 11.273 63.882 12.139 ;
     RECT  18.615 11.975 37.797 12.209 ;
     RECT  40.215 11.975 41.058 12.209 ;
     RECT  55.548 12.047 57.438 12.209 ;
     RECT  59.04 11.399 60.066 12.217 ;
     RECT  53.496 12.077 54.81 12.221 ;
     RECT  47.88 11.237 48.597 12.245 ;
     RECT  56.415 12.209 57.33 12.245 ;
     RECT  42.588 11.981 43.197 12.253 ;
     RECT  59.004 12.217 60.066 12.283 ;
     RECT  54.72 12.221 54.81 12.289 ;
     RECT  55.548 12.209 55.674 12.289 ;
     RECT  58.176 12.047 58.194 12.317 ;
     RECT  3.6 11.543 3.654 12.325 ;
     RECT  4.68 11.741 17.838 12.325 ;
     RECT  40.215 12.209 40.497 12.331 ;
     RECT  54.72 12.289 55.674 12.353 ;
     RECT  45.615 11.705 46.782 12.451 ;
     RECT  59.004 12.283 60.21 12.451 ;
     RECT  61.815 12.139 63.882 12.461 ;
     RECT  18.615 12.209 36.378 12.479 ;
     RECT  38.736 12.325 39.042 12.479 ;
     RECT  59.004 12.451 60.318 12.509 ;
     RECT  37.224 12.209 37.797 12.515 ;
     RECT  55.116 12.353 55.674 12.515 ;
     RECT  59.004 12.509 60.21 12.515 ;
     RECT  38.736 12.479 38.754 12.551 ;
     RECT  52.488 12.289 52.578 12.551 ;
     RECT  55.224 12.515 55.242 12.551 ;
     RECT  40.068 12.331 40.497 12.559 ;
     RECT  61.815 12.461 62.406 12.559 ;
     RECT  45.615 12.451 46.854 12.595 ;
     RECT  59.004 12.515 59.397 12.595 ;
     RECT  63.288 12.461 63.882 12.595 ;
     RECT  44.46 12.523 44.478 12.623 ;
     RECT  45.612 12.595 46.854 12.623 ;
     RECT  2.415 11.669 2.697 12.631 ;
     RECT  3.6 12.325 17.838 12.631 ;
     RECT  63.288 12.595 63.918 12.653 ;
     RECT  52.488 12.551 52.506 12.749 ;
     RECT  45.612 12.623 45.897 12.757 ;
     RECT  50.796 11.975 51.297 12.757 ;
     RECT  39.564 12.559 40.497 12.785 ;
     RECT  42.264 12.253 43.197 12.785 ;
     RECT  53.496 12.221 53.997 12.785 ;
     RECT  58.284 12.595 59.397 12.785 ;
     RECT  61.596 12.559 62.406 12.793 ;
     RECT  63.288 12.653 63.882 12.821 ;
     RECT  50.724 12.757 51.297 12.857 ;
     RECT  52.416 12.757 52.434 12.857 ;
     RECT  63.288 12.821 63.846 12.857 ;
     RECT  2.415 12.631 17.838 12.865 ;
     RECT  18.615 12.479 35.478 12.865 ;
     RECT  2.415 12.865 35.478 12.893 ;
     RECT  39.636 12.785 40.497 12.893 ;
     RECT  45.504 12.757 45.897 12.893 ;
     RECT  46.764 12.623 46.854 12.893 ;
     RECT  58.356 12.785 59.397 12.893 ;
     RECT  41.544 12.829 41.562 12.929 ;
     RECT  48.096 12.245 48.597 13.019 ;
     RECT  2.415 12.893 17.694 13.055 ;
     RECT  53.604 12.785 53.997 13.055 ;
     RECT  2.415 13.055 17.658 13.091 ;
     RECT  39.672 12.893 40.497 13.091 ;
     RECT  63.288 12.857 63.306 13.091 ;
     RECT  5.115 13.091 17.658 13.163 ;
     RECT  18.432 12.893 35.478 13.289 ;
     RECT  61.56 12.793 62.406 13.325 ;
     RECT  61.56 13.325 62.37 13.397 ;
     RECT  20.412 13.289 35.478 13.441 ;
     RECT  20.412 13.441 35.838 13.517 ;
     RECT  61.815 13.397 62.37 13.559 ;
     RECT  61.815 13.559 62.262 13.595 ;
     RECT  17.388 13.163 17.658 13.667 ;
     RECT  20.412 13.517 35.478 13.667 ;
     RECT  2.415 13.091 4.05 13.703 ;
     RECT  3.78 13.703 4.05 13.829 ;
     RECT  18.432 13.289 19.638 13.829 ;
     RECT  3.888 13.829 4.05 13.981 ;
     RECT  5.115 13.163 16.65 13.981 ;
     RECT  5.076 13.981 16.65 14.059 ;
     RECT  18.432 13.829 19.566 14.071 ;
     RECT  2.415 13.703 2.934 14.093 ;
     RECT  3.888 13.981 4.302 14.099 ;
     RECT  3.888 14.099 4.158 14.135 ;
     RECT  5.076 14.059 17.046 14.207 ;
     RECT  3.996 14.135 4.05 14.369 ;
     RECT  20.988 13.667 35.478 14.405 ;
     RECT  5.076 14.207 8.262 14.441 ;
     RECT  9.108 14.207 17.046 14.449 ;
     RECT  37.404 12.515 37.797 14.449 ;
     RECT  9.108 14.449 17.082 14.521 ;
     RECT  9.108 14.521 17.19 14.611 ;
     RECT  18.216 14.071 19.566 14.611 ;
     RECT  20.988 14.405 31.122 14.647 ;
     RECT  32.115 14.405 35.478 14.669 ;
     RECT  20.484 14.647 31.122 14.675 ;
     RECT  5.115 14.441 8.262 15.019 ;
     RECT  9.108 14.611 19.566 15.019 ;
     RECT  37.404 14.449 38.358 15.179 ;
     RECT  4.032 14.369 4.05 15.215 ;
     RECT  5.115 15.019 19.566 15.331 ;
     RECT  20.484 14.675 30.222 15.457 ;
     RECT  20.448 15.457 30.222 15.485 ;
     RECT  40.215 13.091 40.497 15.529 ;
     RECT  4.068 15.331 19.566 15.565 ;
     RECT  20.448 15.485 25.29 15.565 ;
     RECT  4.068 15.565 25.29 15.581 ;
     RECT  31.104 14.675 31.122 15.601 ;
     RECT  32.115 14.669 32.397 15.601 ;
     RECT  26.028 15.485 30.222 15.691 ;
     RECT  31.104 15.601 32.397 15.691 ;
     RECT  61.815 13.595 62.097 15.727 ;
     RECT  4.068 15.581 25.254 15.755 ;
     RECT  33.408 14.669 35.478 15.871 ;
     RECT  33.408 15.871 36.018 15.979 ;
     RECT  39.924 15.529 40.497 15.989 ;
     RECT  59.115 12.893 59.397 16.033 ;
     RECT  2.415 14.093 2.697 16.069 ;
     RECT  40.215 15.989 40.497 16.075 ;
     RECT  37.404 15.179 38.214 16.123 ;
     RECT  58.716 16.033 59.397 16.169 ;
     RECT  26.028 15.691 32.397 16.267 ;
     RECT  33.408 15.979 36.414 16.267 ;
     RECT  42.915 12.785 43.197 16.267 ;
     RECT  25.992 16.267 32.397 16.303 ;
     RECT  33.228 16.267 36.414 16.411 ;
     RECT  37.404 16.123 38.79 16.411 ;
     RECT  2.415 16.069 2.754 16.459 ;
     RECT  2.415 16.459 2.97 16.501 ;
     RECT  4.068 15.755 25.11 16.501 ;
     RECT  25.92 16.303 32.397 16.529 ;
     RECT  33.228 16.411 38.79 16.529 ;
     RECT  60.516 16.105 60.534 16.537 ;
     RECT  0.18 16.501 0.198 16.609 ;
     RECT  33.228 16.529 37.797 16.645 ;
     RECT  38.628 16.529 38.79 16.645 ;
     RECT  60.516 16.537 60.966 16.681 ;
     RECT  61.815 15.727 62.154 16.681 ;
     RECT  26.028 16.529 32.397 16.795 ;
     RECT  33.12 16.645 37.797 16.795 ;
     RECT  38.628 16.645 38.862 16.799 ;
     RECT  2.415 16.501 25.11 16.835 ;
     RECT  0.18 16.609 0.522 16.879 ;
     RECT  45.615 12.893 45.897 16.879 ;
     RECT  26.028 16.795 37.797 16.907 ;
     RECT  37.332 16.907 37.797 16.943 ;
     RECT  0.18 16.879 0.558 16.951 ;
     RECT  40.215 16.075 40.77 16.951 ;
     RECT  38.628 16.799 38.754 17.069 ;
     RECT  60.516 16.681 62.154 17.077 ;
     RECT  22.824 16.835 25.11 17.105 ;
     RECT  37.404 16.943 37.797 17.105 ;
     RECT  2.415 16.835 21.942 17.249 ;
     RECT  0.108 16.951 0.558 17.261 ;
     RECT  0.144 17.261 0.558 17.357 ;
     RECT  22.896 17.105 25.11 17.383 ;
     RECT  40.215 16.951 41.058 17.419 ;
     RECT  42.264 16.267 43.197 17.419 ;
     RECT  0.18 17.357 0.558 17.453 ;
     RECT  46.764 17.347 46.782 17.483 ;
     RECT  26.028 16.907 36.522 17.611 ;
     RECT  25.992 17.611 36.522 17.645 ;
     RECT  25.992 17.645 29.697 17.681 ;
     RECT  37.515 17.105 37.797 17.725 ;
     RECT  2.415 17.249 14.562 17.761 ;
     RECT  38.736 17.069 38.754 17.761 ;
     RECT  48.315 13.019 48.597 17.887 ;
     RECT  15.408 17.249 21.942 17.923 ;
     RECT  30.708 17.645 36.522 17.923 ;
     RECT  40.215 17.419 43.197 17.933 ;
     RECT  30.708 17.923 36.63 17.959 ;
     RECT  37.515 17.725 37.89 17.959 ;
     RECT  15.408 17.923 22.122 17.995 ;
     RECT  38.736 17.761 39.33 17.995 ;
     RECT  30.708 17.959 37.89 18.031 ;
     RECT  38.736 17.995 39.366 18.031 ;
     RECT  15.408 17.995 22.158 18.121 ;
     RECT  22.896 17.383 25.254 18.121 ;
     RECT  60.516 17.077 62.406 18.149 ;
     RECT  2.304 17.761 14.562 18.157 ;
     RECT  15.408 18.121 25.254 18.157 ;
     RECT  61.164 18.149 62.406 18.157 ;
     RECT  61.164 18.157 62.442 18.193 ;
     RECT  0.432 17.453 0.558 18.413 ;
     RECT  45.036 16.879 45.897 18.419 ;
     RECT  30.708 18.031 39.366 18.461 ;
     RECT  2.304 18.157 25.254 18.535 ;
     RECT  26.1 17.681 29.697 18.535 ;
     RECT  30.708 18.461 32.454 18.535 ;
     RECT  30.42 18.535 32.454 18.599 ;
     RECT  40.215 17.933 42.174 18.599 ;
     RECT  48.096 17.887 48.597 18.689 ;
     RECT  42.915 17.933 43.197 18.697 ;
     RECT  53.715 13.055 53.997 18.697 ;
     RECT  61.164 18.193 62.982 18.769 ;
     RECT  42.732 18.697 43.197 18.797 ;
     RECT  2.304 18.535 29.697 18.841 ;
     RECT  30.42 18.599 32.397 18.841 ;
     RECT  53.604 18.697 53.997 18.959 ;
     RECT  59.115 16.169 59.397 18.967 ;
     RECT  46.692 18.967 46.71 19.003 ;
     RECT  48.276 18.689 48.597 19.003 ;
     RECT  2.304 18.841 32.397 19.031 ;
     RECT  51.015 12.857 51.297 19.039 ;
     RECT  33.444 18.461 39.366 19.075 ;
     RECT  40.215 18.599 41.958 19.075 ;
     RECT  61.164 18.769 63.018 19.075 ;
     RECT  46.656 19.003 46.71 19.103 ;
     RECT  9.18 19.031 32.397 19.229 ;
     RECT  42.768 18.797 43.197 19.229 ;
     RECT  46.692 19.103 46.71 19.229 ;
     RECT  2.304 19.031 8.37 19.337 ;
     RECT  9.684 19.229 32.397 19.345 ;
     RECT  9.684 19.345 32.706 19.381 ;
     RECT  33.444 19.075 41.958 19.381 ;
     RECT  61.164 19.075 63.342 19.381 ;
     RECT  9.684 19.381 41.958 19.409 ;
     RECT  0.54 18.413 0.558 19.469 ;
     RECT  9.684 19.409 41.634 19.499 ;
     RECT  60.948 19.381 63.342 19.543 ;
     RECT  48.276 19.003 49.194 19.769 ;
     RECT  53.715 18.959 53.997 19.885 ;
     RECT  0.144 19.723 0.234 19.949 ;
     RECT  9.684 19.499 31.086 19.949 ;
     RECT  46.8 19.651 46.818 20.039 ;
     RECT  55.296 19.813 55.314 20.039 ;
     RECT  3.78 19.337 8.37 20.047 ;
     RECT  9.684 19.949 10.797 20.047 ;
     RECT  42.915 19.229 43.197 20.047 ;
     RECT  60.948 19.543 63.882 20.047 ;
     RECT  48.276 19.769 48.597 20.111 ;
     RECT  56.415 12.245 56.697 20.119 ;
     RECT  11.52 19.949 31.086 20.183 ;
     RECT  2.304 19.337 2.862 20.191 ;
     RECT  3.78 20.047 10.797 20.191 ;
     RECT  58.716 18.967 59.397 20.281 ;
     RECT  11.556 20.183 31.086 20.317 ;
     RECT  53.715 19.885 54.342 20.317 ;
     RECT  32.112 19.499 41.634 20.345 ;
     RECT  60.948 20.047 63.954 20.345 ;
     RECT  55.764 20.119 56.697 20.417 ;
     RECT  60.984 20.345 63.954 20.417 ;
     RECT  53.715 20.317 54.882 20.489 ;
     RECT  56.016 20.417 56.697 20.489 ;
     RECT  11.556 20.317 31.266 20.587 ;
     RECT  11.556 20.587 31.374 20.623 ;
     RECT  32.112 20.345 41.31 20.623 ;
     RECT  50.724 19.039 51.297 20.821 ;
     RECT  11.556 20.623 41.31 20.849 ;
     RECT  42.915 20.047 43.362 20.849 ;
     RECT  58.716 20.281 60.102 20.849 ;
     RECT  26.244 20.849 41.13 20.921 ;
     RECT  61.308 20.417 63.954 20.929 ;
     RECT  2.304 20.191 10.797 20.965 ;
     RECT  11.556 20.849 25.47 20.965 ;
     RECT  42.915 20.849 43.197 20.965 ;
     RECT  50.688 20.821 51.297 20.993 ;
     RECT  58.716 20.849 59.778 20.993 ;
     RECT  45.615 18.419 45.897 21.091 ;
     RECT  47.232 20.659 47.25 21.091 ;
     RECT  45.615 21.091 45.954 21.115 ;
     RECT  46.764 21.091 47.25 21.115 ;
     RECT  61.308 20.929 63.99 21.197 ;
     RECT  61.308 21.197 63.918 21.199 ;
     RECT  26.244 20.921 41.058 21.389 ;
     RECT  45.615 21.115 47.25 21.389 ;
     RECT  49.68 20.893 49.698 21.389 ;
     RECT  55.26 20.923 55.278 21.451 ;
     RECT  53.715 20.489 53.997 21.469 ;
     RECT  55.26 21.451 55.458 21.469 ;
     RECT  0.144 19.949 0.162 21.499 ;
     RECT  46.656 21.389 47.25 21.505 ;
     RECT  53.715 21.469 55.458 21.505 ;
     RECT  46.656 21.505 47.322 21.533 ;
     RECT  0.144 21.499 0.198 21.547 ;
     RECT  26.244 21.389 40.95 21.569 ;
     RECT  53.715 21.505 55.566 21.569 ;
     RECT  0.108 21.547 0.198 21.614 ;
     RECT  0.144 21.614 0.198 21.643 ;
     RECT  42.768 20.965 43.197 21.659 ;
     RECT  50.724 20.993 51.297 21.659 ;
     RECT  54.756 21.569 55.566 21.659 ;
     RECT  54.9 21.659 55.566 21.695 ;
     RECT  48.315 20.111 48.597 21.703 ;
     RECT  60.984 21.199 63.918 21.739 ;
     RECT  0.144 21.643 0.342 21.773 ;
     RECT  2.304 20.965 25.47 21.775 ;
     RECT  26.244 21.569 40.734 21.775 ;
     RECT  46.764 21.533 47.322 21.775 ;
     RECT  48.315 21.703 48.726 21.775 ;
     RECT  56.415 20.489 56.697 21.775 ;
     RECT  59.115 20.993 59.778 21.811 ;
     RECT  44.46 21.163 44.478 21.901 ;
     RECT  45.615 21.389 45.897 21.901 ;
     RECT  2.304 21.775 40.734 21.929 ;
     RECT  42.915 21.659 43.197 21.937 ;
     RECT  22.32 21.929 40.734 21.971 ;
     RECT  53.715 21.569 53.997 21.973 ;
     RECT  44.46 21.901 45.897 22.037 ;
     RECT  45.18 22.037 45.897 22.073 ;
     RECT  54.9 21.695 55.098 22.073 ;
     RECT  59.076 21.811 59.778 22.081 ;
     RECT  53.424 21.973 53.997 22.109 ;
     RECT  0.144 21.773 0.27 22.157 ;
     RECT  46.764 21.775 48.726 22.199 ;
     RECT  46.764 22.199 47.502 22.235 ;
     RECT  54.9 22.073 54.99 22.235 ;
     RECT  55.872 21.775 56.697 22.235 ;
     RECT  59.076 22.081 59.886 22.253 ;
     RECT  42.915 21.937 43.218 22.271 ;
     RECT  46.764 22.235 47.43 22.343 ;
     RECT  60.948 21.739 63.918 22.351 ;
     RECT  0.144 22.157 0.198 22.411 ;
     RECT  60.948 22.351 63.954 22.469 ;
     RECT  56.124 22.235 56.697 22.505 ;
     RECT  54.864 22.477 54.882 22.513 ;
     RECT  51.015 21.659 51.297 22.549 ;
     RECT  46.764 22.343 46.926 22.577 ;
     RECT  54.792 22.513 54.882 22.577 ;
     RECT  56.415 22.505 56.697 22.585 ;
     RECT  2.304 21.929 21.597 22.603 ;
     RECT  60.984 22.469 63.954 22.649 ;
     RECT  22.32 21.971 40.698 22.711 ;
     RECT  61.056 22.649 63.954 22.733 ;
     RECT  48.315 22.199 48.726 22.739 ;
     RECT  2.268 22.603 21.597 22.747 ;
     RECT  22.32 22.711 40.986 22.747 ;
     RECT  2.268 22.747 40.986 22.811 ;
     RECT  59.076 22.253 59.454 22.819 ;
     RECT  7.74 22.811 40.986 22.843 ;
     RECT  2.268 22.811 6.858 22.847 ;
     RECT  7.74 22.843 41.166 22.919 ;
     RECT  61.056 22.733 63.918 22.925 ;
     RECT  50.724 22.549 51.297 22.981 ;
     RECT  54.792 22.577 54.81 22.981 ;
     RECT  0.108 22.411 0.198 22.987 ;
     RECT  58.716 22.819 59.454 23.009 ;
     RECT  58.716 23.009 59.397 23.017 ;
     RECT  42.915 22.271 43.197 23.089 ;
     RECT  58.428 23.017 59.397 23.089 ;
     RECT  54.72 22.981 54.81 23.117 ;
     RECT  56.415 22.585 57.042 23.117 ;
     RECT  48.315 22.739 48.597 23.125 ;
     RECT  7.74 22.919 41.094 23.153 ;
     RECT  58.356 23.089 59.397 23.161 ;
     RECT  7.74 23.153 41.022 23.189 ;
     RECT  47.952 23.125 48.597 23.279 ;
     RECT  50.688 22.981 51.297 23.279 ;
     RECT  54.72 23.117 54.738 23.279 ;
     RECT  0.108 22.987 0.342 23.309 ;
     RECT  2.304 22.847 6.858 23.315 ;
     RECT  58.248 23.161 59.397 23.315 ;
     RECT  2.304 23.315 4.23 23.351 ;
     RECT  46.908 22.577 46.926 23.351 ;
     RECT  50.796 23.279 51.297 23.351 ;
     RECT  2.304 23.351 4.086 23.459 ;
     RECT  7.74 23.189 40.95 23.549 ;
     RECT  49.68 23.395 49.698 23.549 ;
     RECT  2.415 23.459 4.086 23.585 ;
     RECT  5.076 23.315 6.858 23.629 ;
     RECT  7.74 23.549 40.59 23.629 ;
     RECT  2.415 23.585 3.726 23.819 ;
     RECT  5.076 23.629 40.59 23.855 ;
     RECT  61.056 22.925 63.882 23.863 ;
     RECT  48.315 23.279 48.597 23.899 ;
     RECT  2.415 23.819 3.114 23.927 ;
     RECT  42.768 23.089 43.197 23.971 ;
     RECT  58.716 23.315 59.397 23.971 ;
     RECT  60.516 23.863 63.882 23.971 ;
     RECT  48.315 23.899 49.626 24.089 ;
     RECT  58.716 23.971 63.882 24.089 ;
     RECT  51.015 23.351 51.297 24.133 ;
     RECT  2.415 23.927 3.006 24.161 ;
     RECT  53.715 22.109 53.997 24.169 ;
     RECT  46.764 23.593 46.782 24.241 ;
     RECT  42.66 23.971 43.197 24.269 ;
     RECT  53.715 24.169 54.594 24.269 ;
     RECT  58.752 24.089 63.882 24.269 ;
     RECT  7.776 23.855 40.59 24.359 ;
     RECT  46.764 24.241 46.818 24.359 ;
     RECT  50.652 24.133 51.297 24.359 ;
     RECT  45.615 22.073 45.897 24.367 ;
     RECT  7.812 24.359 40.59 24.503 ;
     RECT  7.812 24.503 40.497 24.509 ;
     RECT  58.752 24.269 63.486 24.629 ;
     RECT  60.12 24.629 63.486 24.665 ;
     RECT  42.915 24.269 43.197 24.709 ;
     RECT  5.115 23.855 6.858 24.745 ;
     RECT  51.012 24.359 51.297 24.773 ;
     RECT  60.624 24.665 63.486 24.773 ;
     RECT  5.115 24.745 6.93 24.781 ;
     RECT  50.184 24.439 50.274 24.809 ;
     RECT  45.036 24.367 45.897 24.907 ;
     RECT  50.256 24.809 50.274 24.908 ;
     RECT  46.764 24.359 46.782 25.079 ;
     RECT  60.624 24.773 63.378 25.079 ;
     RECT  5.004 24.781 6.93 25.141 ;
     RECT  7.812 24.509 11.394 25.141 ;
     RECT  58.752 24.629 59.397 25.141 ;
     RECT  5.004 25.141 11.394 25.229 ;
     RECT  58.572 25.141 59.397 25.229 ;
     RECT  42.915 24.709 43.506 25.249 ;
     RECT  5.115 25.229 11.394 25.285 ;
     RECT  12.348 24.509 40.497 25.285 ;
     RECT  42.732 25.249 43.506 25.349 ;
     RECT  44.676 24.907 45.897 25.475 ;
     RECT  5.115 25.285 40.554 25.511 ;
     RECT  44.892 25.475 45.897 25.547 ;
     RECT  42.768 25.349 43.506 25.583 ;
     RECT  42.915 25.583 43.506 25.619 ;
     RECT  60.876 25.079 63.378 25.675 ;
     RECT  44.964 25.547 45.897 25.951 ;
     RECT  46.764 25.861 46.782 25.951 ;
     RECT  5.115 25.511 40.497 26.087 ;
     RECT  44.964 25.951 46.782 26.095 ;
     RECT  44.964 26.095 47.286 26.123 ;
     RECT  5.115 26.087 17.658 26.159 ;
     RECT  18.468 26.087 40.497 26.159 ;
     RECT  46.692 26.123 47.286 26.159 ;
     RECT  60.876 25.675 63.846 26.221 ;
     RECT  47.268 26.159 47.286 26.249 ;
     RECT  17.064 26.159 17.658 26.285 ;
     RECT  60.804 26.221 63.846 26.393 ;
     RECT  43.992 26.131 44.01 26.491 ;
     RECT  43.992 26.491 44.118 26.555 ;
     RECT  58.716 25.229 59.397 26.591 ;
     RECT  42.915 25.619 43.197 26.599 ;
     RECT  44.1 26.555 44.118 26.627 ;
     RECT  48.315 24.089 48.597 26.671 ;
     RECT  5.115 26.159 16.197 26.789 ;
     RECT  17.064 26.285 17.082 26.789 ;
     RECT  60.984 26.393 63.846 26.789 ;
     RECT  44.964 26.123 45.897 26.825 ;
     RECT  5.115 26.789 5.958 26.861 ;
     RECT  6.696 26.789 11.898 26.861 ;
     RECT  48.315 26.671 48.834 26.933 ;
     RECT  18.576 26.159 40.497 26.969 ;
     RECT  61.524 26.789 63.846 26.969 ;
     RECT  5.115 26.861 5.922 27.059 ;
     RECT  6.696 26.861 6.714 27.059 ;
     RECT  23.328 26.969 40.497 27.059 ;
     RECT  5.115 27.059 5.778 27.095 ;
     RECT  23.328 27.059 24.462 27.095 ;
     RECT  25.2 27.059 36.234 27.095 ;
     RECT  13.215 26.789 16.197 27.131 ;
     RECT  17.46 27.139 17.478 27.163 ;
     RECT  23.328 27.095 24.426 27.167 ;
     RECT  23.328 27.167 24.39 27.203 ;
     RECT  25.2 27.095 35.946 27.203 ;
     RECT  17.46 27.163 17.586 27.211 ;
     RECT  18.576 26.969 22.518 27.211 ;
     RECT  23.472 27.203 24.39 27.239 ;
     RECT  25.2 27.203 35.838 27.239 ;
     RECT  37.08 27.059 40.497 27.239 ;
     RECT  42.915 26.599 43.362 27.239 ;
     RECT  61.524 26.969 63.27 27.239 ;
     RECT  9.18 26.861 11.898 27.329 ;
     RECT  17.46 27.211 22.518 27.329 ;
     RECT  25.2 27.239 32.742 27.329 ;
     RECT  33.552 27.239 35.838 27.329 ;
     RECT  9.18 27.329 11.754 27.365 ;
     RECT  13.215 27.131 15.174 27.365 ;
     RECT  17.568 27.329 22.482 27.365 ;
     RECT  23.472 27.239 24.297 27.365 ;
     RECT  25.2 27.329 32.598 27.365 ;
     RECT  33.552 27.329 35.694 27.365 ;
     RECT  37.332 27.239 40.497 27.365 ;
     RECT  61.704 27.239 63.054 27.365 ;
     RECT  9.684 27.365 11.574 27.389 ;
     RECT  18.144 27.365 22.482 27.401 ;
     RECT  31.536 27.365 32.397 27.401 ;
     RECT  22.464 27.401 22.482 27.437 ;
     RECT  25.2 27.365 28.278 27.473 ;
     RECT  2.415 24.161 2.697 27.557 ;
     RECT  5.115 27.095 5.397 27.557 ;
     RECT  7.815 26.861 8.097 27.557 ;
     RECT  13.215 27.365 14.886 27.557 ;
     RECT  15.915 27.131 16.197 27.557 ;
     RECT  24.015 27.365 24.297 27.557 ;
     RECT  33.588 27.365 35.694 27.557 ;
     RECT  37.515 27.365 37.797 27.557 ;
     RECT  42.915 27.239 43.197 27.557 ;
     RECT  45.615 26.825 45.897 27.557 ;
     RECT  48.315 26.933 48.597 27.557 ;
     RECT  51.015 24.773 51.297 27.557 ;
     RECT  53.715 24.269 53.997 27.557 ;
     RECT  56.415 23.117 56.697 27.557 ;
     RECT  59.115 26.591 59.397 27.557 ;
     RECT  61.815 27.365 63.054 27.557 ;
     RECT  13.407 27.557 14.886 27.599 ;
     RECT  25.2 27.473 27.486 27.599 ;
     RECT  28.26 27.473 28.278 27.599 ;
     RECT  30.636 27.365 30.798 27.599 ;
     RECT  35.007 27.557 35.694 27.599 ;
     RECT  62.007 27.557 63.054 27.599 ;
     RECT  9.684 27.389 11.43 27.635 ;
     RECT  18.144 27.401 21.597 27.635 ;
     RECT  26.064 27.599 27.306 27.635 ;
     RECT  29.124 27.365 29.697 27.635 ;
     RECT  30.636 27.599 30.654 27.635 ;
     RECT  31.608 27.401 32.397 27.635 ;
     RECT  35.007 27.599 35.586 27.635 ;
     RECT  39.168 27.365 40.497 27.635 ;
     RECT  33.588 27.557 34.11 27.671 ;
     RECT  33.66 27.671 34.11 27.707 ;
     RECT  10.707 27.635 11.43 27.743 ;
     RECT  18.144 27.635 18.99 27.743 ;
     RECT  19.728 27.635 21.597 27.743 ;
     RECT  63.036 27.599 63.054 27.743 ;
     RECT  20.304 27.743 21.597 27.779 ;
     RECT  26.064 27.635 26.082 27.779 ;
     RECT  33.66 27.707 33.678 27.779 ;
     RECT  2.607 27.557 2.697 27.827 ;
     RECT  5.307 27.557 5.397 27.827 ;
     RECT  8.007 27.557 8.097 27.827 ;
     RECT  10.707 27.743 10.797 27.827 ;
     RECT  13.407 27.599 14.526 27.827 ;
     RECT  16.107 27.557 16.197 27.827 ;
     RECT  18.144 27.743 18.897 27.827 ;
     RECT  21.507 27.779 21.597 27.827 ;
     RECT  24.207 27.557 24.297 27.827 ;
     RECT  26.907 27.635 26.997 27.827 ;
     RECT  29.607 27.635 29.697 27.827 ;
     RECT  32.307 27.635 32.397 27.827 ;
     RECT  35.007 27.635 35.097 27.827 ;
     RECT  37.707 27.557 37.797 27.827 ;
     RECT  40.407 27.635 40.497 27.827 ;
     RECT  43.107 27.557 43.197 27.827 ;
     RECT  45.807 27.557 45.897 27.827 ;
     RECT  48.507 27.557 48.597 27.827 ;
     RECT  51.207 27.557 51.297 27.827 ;
     RECT  53.907 27.557 53.997 27.827 ;
     RECT  56.607 27.557 56.697 27.827 ;
     RECT  59.307 27.557 59.397 27.827 ;
     RECT  62.007 27.599 62.097 27.827 ;
     RECT  18.144 27.827 18.162 27.869 ;
     RECT  20.304 27.779 20.322 27.869 ;
     RECT  14.004 27.827 14.526 29.659 ;
     RECT  13.86 29.659 14.526 30.091 ;
     RECT  13.788 30.091 14.526 30.137 ;
     RECT  13.86 30.137 14.526 30.204 ;
    LAYER M4 ;
     RECT  0.06 17.232 0.133 23.304 ;
     RECT  0.133 17.232 0.137 23.352 ;
     RECT  0.137 17.328 0.173 23.352 ;
     RECT  0.173 17.424 0.209 23.352 ;
     RECT  0.06 4.176 0.245 10.248 ;
     RECT  0.245 4.176 0.569 10.152 ;
     RECT  0.569 4.464 2.408 10.152 ;
     RECT  0.209 17.52 2.408 23.352 ;
     RECT  2.408 2.148 2.512 27.552 ;
     RECT  2.512 2.418 2.6 27.552 ;
     RECT  2.6 2.418 2.704 27.822 ;
     RECT  2.704 16.464 3.161 23.352 ;
     RECT  2.704 4.368 3.377 10.872 ;
     RECT  3.377 10.8 3.413 10.872 ;
     RECT  3.913 11.376 4.021 11.4 ;
     RECT  2.704 14.064 4.021 14.088 ;
     RECT  3.377 4.368 4.273 9.72 ;
     RECT  4.021 11.376 4.549 12.36 ;
     RECT  4.273 4.176 4.741 9.72 ;
     RECT  4.741 4.176 4.813 10.344 ;
     RECT  3.161 16.464 4.837 23.208 ;
     RECT  4.813 4.176 4.921 10.392 ;
     RECT  4.921 3.984 4.933 10.392 ;
     RECT  4.549 11.376 4.933 13.08 ;
     RECT  4.981 2.784 5.108 2.808 ;
     RECT  4.933 3.888 5.108 13.08 ;
     RECT  4.021 14.064 5.108 14.856 ;
     RECT  4.837 16.032 5.108 23.208 ;
     RECT  4.993 25.2 5.108 25.224 ;
     RECT  5.108 2.148 5.212 27.552 ;
     RECT  5.212 2.418 5.3 27.552 ;
     RECT  5.3 2.418 5.404 27.822 ;
     RECT  5.404 13.104 5.501 23.544 ;
     RECT  5.501 13.392 5.644 23.544 ;
     RECT  5.644 13.392 6.041 23.352 ;
     RECT  5.404 2.736 6.541 11.832 ;
     RECT  6.541 2.736 6.721 11.976 ;
     RECT  6.041 13.392 6.721 14.136 ;
     RECT  6.041 15.264 7.045 23.352 ;
     RECT  7.045 15.264 7.573 23.832 ;
     RECT  7.573 15.264 7.669 23.88 ;
     RECT  5.404 25.2 7.669 25.224 ;
     RECT  5.404 26.352 7.669 26.856 ;
     RECT  6.721 2.736 7.693 14.136 ;
     RECT  7.693 2.592 7.808 14.136 ;
     RECT  7.669 15.264 7.808 26.856 ;
     RECT  7.808 2.148 7.912 27.552 ;
     RECT  7.912 2.418 8 27.552 ;
     RECT  8 2.418 8.104 27.822 ;
     RECT  8.104 15.024 8.243 24.456 ;
     RECT  8.243 15.024 8.245 19.704 ;
     RECT  8.243 20.688 8.273 24.456 ;
     RECT  8.104 2.418 8.381 13.464 ;
     RECT  8.273 20.688 8.381 22.776 ;
     RECT  8.245 15.024 8.417 19.656 ;
     RECT  8.381 2.418 8.453 8.184 ;
     RECT  8.417 15.024 8.597 17.928 ;
     RECT  8.381 20.832 8.956 22.776 ;
     RECT  8.453 2.418 8.989 7.704 ;
     RECT  8.381 9.216 9.107 13.464 ;
     RECT  9.107 10.896 9.209 13.464 ;
     RECT  8.597 15.744 9.209 17.928 ;
     RECT  8.273 23.856 9.349 24.456 ;
     RECT  8.104 25.872 9.461 26.856 ;
     RECT  8.956 20.832 9.493 21.048 ;
     RECT  9.349 23.856 9.541 24.504 ;
     RECT  9.461 25.872 9.541 26.52 ;
     RECT  9.107 9.216 9.601 9.864 ;
     RECT  9.209 15.792 9.601 17.928 ;
     RECT  8.989 2.304 9.637 7.704 ;
     RECT  8.956 22.56 9.781 22.776 ;
     RECT  9.541 23.856 9.781 26.52 ;
     RECT  9.781 22.56 9.961 26.52 ;
     RECT  9.601 15.792 10.105 18.216 ;
     RECT  8.417 19.584 10.105 19.656 ;
     RECT  9.493 20.736 10.141 21.048 ;
     RECT  9.601 9.168 10.357 9.864 ;
     RECT  9.637 2.304 10.393 7.8 ;
     RECT  10.357 8.976 10.393 9.864 ;
     RECT  10.393 2.304 10.429 9.864 ;
     RECT  9.209 10.896 10.429 13.128 ;
     RECT  10.429 2.304 10.508 13.128 ;
     RECT  10.177 14.736 10.508 14.76 ;
     RECT  10.105 15.792 10.508 19.656 ;
     RECT  10.141 20.736 10.508 21.096 ;
     RECT  9.961 22.464 10.508 26.52 ;
     RECT  10.508 2.148 10.612 27.552 ;
     RECT  10.612 2.418 10.7 27.552 ;
     RECT  10.7 2.418 10.804 27.822 ;
     RECT  10.804 13.92 10.865 19.944 ;
     RECT  10.865 15.312 10.931 19.944 ;
     RECT  10.804 2.88 11.189 11.976 ;
     RECT  10.804 27.36 11.585 27.384 ;
     RECT  10.865 13.92 11.941 13.944 ;
     RECT  10.931 15.744 11.941 19.944 ;
     RECT  11.189 2.88 12.157 3.96 ;
     RECT  11.189 4.992 12.157 11.976 ;
     RECT  12.157 2.88 12.193 11.976 ;
     RECT  12.193 2.88 12.229 12.264 ;
     RECT  11.941 13.92 12.229 19.944 ;
     RECT  12.229 2.88 12.265 19.944 ;
     RECT  10.804 20.928 12.265 26.28 ;
     RECT  12.265 2.88 12.517 26.28 ;
     RECT  12.517 2.88 13.021 26.376 ;
     RECT  13.021 2.832 13.201 26.376 ;
     RECT  13.201 2.784 13.208 26.376 ;
     RECT  13.208 2.148 13.312 27.552 ;
     RECT  13.312 2.418 13.4 27.552 ;
     RECT  13.4 2.418 13.504 27.822 ;
     RECT  13.504 2.592 13.756 12.072 ;
     RECT  11.221 29.664 13.777 29.688 ;
     RECT  13.777 29.664 13.889 30.12 ;
     RECT  13.889 30.096 14.003 30.12 ;
     RECT  13.504 13.536 14.069 27.192 ;
     RECT  14.069 13.872 14.195 27.192 ;
     RECT  14.195 13.872 14.285 25.8 ;
     RECT  13.756 2.592 14.645 3.96 ;
     RECT  14.645 2.832 14.717 3.96 ;
     RECT  14.285 14.976 14.717 25.8 ;
     RECT  13.756 4.944 14.753 12.072 ;
     RECT  14.753 10.848 15.073 12.072 ;
     RECT  14.717 2.88 15.253 3.96 ;
     RECT  14.753 4.944 15.253 9.864 ;
     RECT  14.285 13.872 15.26 13.896 ;
     RECT  14.717 19.344 15.361 25.8 ;
     RECT  15.26 13.872 15.577 13.992 ;
     RECT  15.073 10.848 15.781 12.36 ;
     RECT  15.577 13.632 15.781 13.992 ;
     RECT  15.253 2.88 15.908 9.864 ;
     RECT  15.781 10.848 15.908 13.992 ;
     RECT  14.717 14.976 15.908 18.216 ;
     RECT  15.361 19.344 15.908 25.848 ;
     RECT  14.195 27.168 15.908 27.192 ;
     RECT  15.908 2.148 16.012 27.552 ;
     RECT  16.012 2.418 16.1 27.552 ;
     RECT  16.1 2.418 16.204 27.822 ;
     RECT  16.204 2.496 17.197 12.36 ;
     RECT  16.204 13.584 17.197 26.136 ;
     RECT  17.197 2.496 17.201 26.136 ;
     RECT  17.201 2.496 17.309 26.088 ;
     RECT  17.309 2.496 18.608 25.8 ;
     RECT  16.204 27.168 18.608 27.192 ;
     RECT  18.608 2.148 18.712 27.552 ;
     RECT  18.712 2.418 18.8 27.552 ;
     RECT  18.8 2.418 18.904 27.822 ;
     RECT  18.904 14.976 19.091 27.192 ;
     RECT  19.091 14.976 19.145 27.144 ;
     RECT  18.904 2.688 19.433 13.896 ;
     RECT  19.433 2.688 19.469 8.28 ;
     RECT  19.469 2.688 19.685 3.96 ;
     RECT  19.685 2.832 19.757 3.96 ;
     RECT  19.145 14.976 20.221 26.808 ;
     RECT  19.469 4.992 20.653 8.28 ;
     RECT  19.433 9.264 20.653 13.896 ;
     RECT  19.757 2.88 20.677 3.96 ;
     RECT  20.653 4.992 20.677 13.896 ;
     RECT  20.221 14.976 20.689 26.904 ;
     RECT  20.677 2.88 21.308 13.896 ;
     RECT  20.689 14.976 21.308 27.144 ;
     RECT  21.308 2.148 21.412 27.552 ;
     RECT  21.412 2.418 21.5 27.552 ;
     RECT  21.5 2.418 21.604 27.822 ;
     RECT  21.604 14.976 21.772 26.808 ;
     RECT  21.772 14.976 22.205 18.216 ;
     RECT  22.205 15.216 22.673 18.216 ;
     RECT  21.604 4.992 22.961 13.896 ;
     RECT  22.673 15.216 23.269 18.024 ;
     RECT  21.604 2.88 23.317 3.96 ;
     RECT  23.317 2.496 23.785 3.96 ;
     RECT  22.961 4.992 23.785 9.576 ;
     RECT  22.961 10.944 23.797 13.896 ;
     RECT  23.269 14.976 23.797 18.024 ;
     RECT  23.785 2.496 24.008 9.576 ;
     RECT  23.797 10.944 24.008 18.024 ;
     RECT  21.772 19.536 24.008 26.808 ;
     RECT  24.008 2.148 24.112 27.552 ;
     RECT  24.112 2.418 24.2 27.552 ;
     RECT  24.2 2.418 24.304 27.822 ;
     RECT  24.304 2.496 24.617 13.656 ;
     RECT  24.304 15.216 24.689 26.856 ;
     RECT  24.689 15.264 24.797 26.856 ;
     RECT  24.797 15.36 25.193 26.856 ;
     RECT  24.617 10.944 25.405 13.656 ;
     RECT  24.617 2.496 26.708 9.576 ;
     RECT  25.405 10.944 26.708 14.232 ;
     RECT  25.193 15.456 26.708 26.856 ;
     RECT  26.708 2.148 26.812 27.552 ;
     RECT  26.812 2.418 26.9 27.552 ;
     RECT  26.9 2.418 27.004 27.822 ;
     RECT  27.004 2.496 27.101 14.424 ;
     RECT  27.004 15.84 27.317 27.384 ;
     RECT  27.317 15.84 27.353 27.096 ;
     RECT  27.101 2.88 28.321 14.424 ;
     RECT  27.353 16.08 28.429 27.096 ;
     RECT  28.321 2.88 28.609 14.52 ;
     RECT  28.429 15.984 28.717 27.096 ;
     RECT  28.609 2.784 28.837 14.52 ;
     RECT  28.717 15.552 28.837 27.096 ;
     RECT  28.837 2.784 29.408 27.096 ;
     RECT  29.408 2.148 29.512 27.552 ;
     RECT  29.512 2.418 29.6 27.552 ;
     RECT  29.6 2.418 29.704 27.822 ;
     RECT  29.704 2.88 29.873 18.024 ;
     RECT  29.873 2.88 29.909 14.52 ;
     RECT  29.704 27.072 29.981 27.096 ;
     RECT  29.873 15.552 30.161 18.024 ;
     RECT  29.909 4.992 30.665 14.52 ;
     RECT  30.161 15.696 30.809 18.024 ;
     RECT  30.809 15.792 30.845 18.024 ;
     RECT  30.665 4.992 30.851 14.424 ;
     RECT  29.704 19.536 30.953 26.04 ;
     RECT  29.909 3.072 31.021 3.96 ;
     RECT  31.021 2.64 31.273 3.96 ;
     RECT  30.851 4.992 31.273 14.184 ;
     RECT  30.953 19.536 31.741 23.688 ;
     RECT  30.953 24.72 31.741 26.04 ;
     RECT  30.845 15.984 31.957 18.024 ;
     RECT  31.741 19.392 32.101 23.688 ;
     RECT  31.741 24.72 32.101 26.232 ;
     RECT  31.273 2.64 32.108 14.184 ;
     RECT  31.957 15.984 32.108 18.168 ;
     RECT  32.101 19.392 32.108 26.232 ;
     RECT  32.108 2.148 32.212 27.552 ;
     RECT  32.212 2.418 32.3 27.552 ;
     RECT  32.3 2.418 32.404 27.822 ;
     RECT  32.404 15.984 33.011 18.456 ;
     RECT  32.404 3.36 33.113 14.664 ;
     RECT  33.113 3.36 33.473 14.328 ;
     RECT  32.404 19.536 33.541 26.04 ;
     RECT  32.404 27.168 33.541 27.192 ;
     RECT  33.473 3.36 33.781 14.28 ;
     RECT  33.781 3.216 34.808 14.28 ;
     RECT  33.011 16.032 34.808 18.456 ;
     RECT  33.541 19.536 34.808 27.192 ;
     RECT  34.808 2.148 34.912 27.552 ;
     RECT  34.912 2.418 35 27.552 ;
     RECT  35 2.418 35.104 27.822 ;
     RECT  35.104 5.04 35.363 13.608 ;
     RECT  35.363 13.488 35.891 13.608 ;
     RECT  35.104 3.36 35.993 3.912 ;
     RECT  35.363 5.088 36.035 12.36 ;
     RECT  36.035 5.712 36.137 12.36 ;
     RECT  35.104 15.984 36.425 27.192 ;
     RECT  35.993 3.36 37.508 3.384 ;
     RECT  36.137 6.048 37.508 12.36 ;
     RECT  36.425 16.032 37.508 27.192 ;
     RECT  37.508 2.148 37.612 27.552 ;
     RECT  37.612 2.418 37.7 27.552 ;
     RECT  37.7 2.418 37.804 27.822 ;
     RECT  37.804 6.048 37.901 12.36 ;
     RECT  37.804 19.344 37.937 25.8 ;
     RECT  37.804 26.784 38.009 27.192 ;
     RECT  37.937 19.392 38.261 25.8 ;
     RECT  38.261 19.392 38.621 25.56 ;
     RECT  38.621 20.544 38.729 25.56 ;
     RECT  38.009 26.88 38.945 27.192 ;
     RECT  38.729 20.544 39.161 25.512 ;
     RECT  37.804 3.36 40.208 3.384 ;
     RECT  37.901 6.048 40.208 9.384 ;
     RECT  37.901 10.944 40.208 12.36 ;
     RECT  37.804 16.08 40.208 16.296 ;
     RECT  37.804 17.424 40.208 18.024 ;
     RECT  38.621 19.392 40.208 19.416 ;
     RECT  39.161 20.88 40.208 25.512 ;
     RECT  38.945 26.928 40.208 27.192 ;
     RECT  40.208 2.148 40.312 27.552 ;
     RECT  40.312 2.418 40.4 27.552 ;
     RECT  40.4 2.418 40.504 27.822 ;
     RECT  40.504 21.12 40.601 23.304 ;
     RECT  40.601 21.12 40.745 23.064 ;
     RECT  40.504 16.08 40.781 16.296 ;
     RECT  40.745 22.848 41.105 23.064 ;
     RECT  41.105 22.848 41.177 22.872 ;
     RECT  40.504 6.048 41.321 9.384 ;
     RECT  40.504 17.424 41.753 17.928 ;
     RECT  40.504 3.36 42.908 3.384 ;
     RECT  41.321 6.048 42.908 7.416 ;
     RECT  41.321 9.024 42.908 9.384 ;
     RECT  40.504 10.944 42.908 12.312 ;
     RECT  40.781 16.272 42.908 16.296 ;
     RECT  41.753 17.904 42.908 17.928 ;
     RECT  40.745 21.12 42.908 21.528 ;
     RECT  40.504 25.2 42.908 25.512 ;
     RECT  42.908 2.148 43.012 27.552 ;
     RECT  43.012 2.418 43.1 27.552 ;
     RECT  43.1 2.418 43.204 27.822 ;
     RECT  43.204 6.336 43.265 7.416 ;
     RECT  43.204 3.36 43.589 3.384 ;
     RECT  43.265 7.152 43.661 7.416 ;
     RECT  43.204 9.024 43.661 9.384 ;
     RECT  43.204 10.944 43.661 12.312 ;
     RECT  43.661 7.2 44.093 7.416 ;
     RECT  43.661 10.992 45.493 12.312 ;
     RECT  44.093 7.392 45.608 7.416 ;
     RECT  43.661 9.072 45.608 9.384 ;
     RECT  45.493 10.992 45.608 12.888 ;
     RECT  43.204 21.12 45.608 21.528 ;
     RECT  43.204 25.2 45.608 25.512 ;
     RECT  45.608 2.148 45.712 27.552 ;
     RECT  45.712 2.418 45.8 27.552 ;
     RECT  45.8 2.418 45.904 27.822 ;
     RECT  45.904 21.12 46.253 21.528 ;
     RECT  45.904 12.288 46.397 12.312 ;
     RECT  45.904 9.072 46.937 9.096 ;
     RECT  45.904 10.992 48.308 11.256 ;
     RECT  46.253 21.504 48.308 21.528 ;
     RECT  45.904 25.2 48.308 25.512 ;
     RECT  48.308 2.148 48.412 27.552 ;
     RECT  48.412 2.418 48.5 27.552 ;
     RECT  48.5 2.418 48.604 27.822 ;
     RECT  48.604 10.992 49.421 11.256 ;
     RECT  49.421 11.232 50.749 11.256 ;
     RECT  50.749 10.992 51.008 11.688 ;
     RECT  48.604 21.504 51.008 21.528 ;
     RECT  48.604 25.2 51.008 25.512 ;
     RECT  51.008 2.148 51.112 27.552 ;
     RECT  51.112 2.418 51.2 27.552 ;
     RECT  51.2 2.418 51.304 27.822 ;
     RECT  51.304 10.992 52.405 11.256 ;
     RECT  52.549 7.68 52.765 7.704 ;
     RECT  52.405 10.128 53.161 11.256 ;
     RECT  52.765 7.44 53.197 7.704 ;
     RECT  53.197 7.152 53.708 7.704 ;
     RECT  53.161 10.128 53.708 12.072 ;
     RECT  51.304 21.504 53.708 21.528 ;
     RECT  51.304 25.2 53.708 25.512 ;
     RECT  53.708 2.148 53.812 27.552 ;
     RECT  53.812 2.418 53.9 27.552 ;
     RECT  53.9 2.418 54.004 27.822 ;
     RECT  54.004 10.128 54.997 12.312 ;
     RECT  54.004 20.4 55.249 20.424 ;
     RECT  54.004 21.504 55.249 22.008 ;
     RECT  54.004 7.152 55.321 7.944 ;
     RECT  54.997 9.264 55.645 12.312 ;
     RECT  55.321 6.288 56.408 7.944 ;
     RECT  55.645 9.264 56.408 12.504 ;
     RECT  55.249 20.4 56.408 22.008 ;
     RECT  54.004 25.2 56.408 25.512 ;
     RECT  56.408 2.148 56.512 27.552 ;
     RECT  56.512 2.418 56.6 27.552 ;
     RECT  56.6 2.418 56.704 27.822 ;
     RECT  56.704 6.288 59.108 7.944 ;
     RECT  56.704 9.264 59.108 12.504 ;
     RECT  56.704 20.928 59.108 22.008 ;
     RECT  56.704 25.2 59.108 25.512 ;
     RECT  59.108 2.148 59.212 27.552 ;
     RECT  59.212 2.418 59.3 27.552 ;
     RECT  59.3 2.418 59.404 27.822 ;
     RECT  59.404 6.288 60.221 7.992 ;
     RECT  59.404 9.264 60.329 12.504 ;
     RECT  60.221 6.864 60.433 7.992 ;
     RECT  60.433 6.864 60.937 8.04 ;
     RECT  60.329 9.264 60.937 12.312 ;
     RECT  59.404 20.928 61.189 22.248 ;
     RECT  61.189 20.928 61.513 22.296 ;
     RECT  61.441 23.328 61.513 23.352 ;
     RECT  61.513 20.928 61.765 23.352 ;
     RECT  61.405 24.48 61.765 24.504 ;
     RECT  60.937 6.864 61.808 12.312 ;
     RECT  61.765 20.928 61.808 24.504 ;
     RECT  59.404 25.488 61.808 25.512 ;
     RECT  61.808 2.148 61.912 27.552 ;
     RECT  61.912 2.418 62 27.552 ;
     RECT  62 2.418 62.104 27.822 ;
     RECT  62.104 20.016 63.241 25.896 ;
     RECT  62.104 6.864 63.277 12.84 ;
     RECT  63.241 20.016 63.853 25.992 ;
     RECT  63.277 6.864 64.716 12.936 ;
     RECT  63.853 19.92 64.716 25.992 ;
     RECT  64.716 7.2 64.757 10.2 ;
    LAYER M5 ;
     RECT  2.4 2.137 2.52 2.151 ;
     RECT  5.1 2.137 5.22 2.151 ;
     RECT  7.8 2.137 7.92 2.151 ;
     RECT  10.5 2.137 10.62 2.151 ;
     RECT  13.2 2.137 13.32 2.151 ;
     RECT  15.9 2.137 16.02 2.151 ;
     RECT  18.6 2.137 18.72 2.151 ;
     RECT  21.3 2.137 21.42 2.151 ;
     RECT  24 2.137 24.12 2.151 ;
     RECT  26.7 2.137 26.82 2.151 ;
     RECT  29.4 2.137 29.52 2.151 ;
     RECT  32.1 2.137 32.22 2.151 ;
     RECT  34.8 2.137 34.92 2.151 ;
     RECT  37.5 2.137 37.62 2.151 ;
     RECT  40.2 2.137 40.32 2.151 ;
     RECT  42.9 2.137 43.02 2.151 ;
     RECT  45.6 2.137 45.72 2.151 ;
     RECT  48.3 2.137 48.42 2.151 ;
     RECT  51 2.137 51.12 2.151 ;
     RECT  53.7 2.137 53.82 2.151 ;
     RECT  56.4 2.137 56.52 2.151 ;
     RECT  59.1 2.137 59.22 2.151 ;
     RECT  61.8 2.137 61.92 2.151 ;
     RECT  32.1 2.151 32.412 2.629 ;
     RECT  5.1 2.151 5.412 2.773 ;
     RECT  4.992 2.773 5.412 2.821 ;
     RECT  18.6 2.151 18.912 3.301 ;
     RECT  17.184 2.485 17.208 3.539 ;
     RECT  34.8 2.151 35.112 3.685 ;
     RECT  4.992 2.821 5.688 3.877 ;
     RECT  13.2 2.151 13.512 3.877 ;
     RECT  33.792 3.205 33.816 4.259 ;
     RECT  4.944 3.877 5.688 4.357 ;
     RECT  4.08 4.357 5.688 4.501 ;
     RECT  10.5 2.151 10.812 4.501 ;
     RECT  21.3 2.151 21.612 4.501 ;
     RECT  18.6 3.301 19.416 4.595 ;
     RECT  25.632 3.157 25.656 4.595 ;
     RECT  31.344 2.629 32.412 4.837 ;
     RECT  9.552 4.501 10.812 4.933 ;
     RECT  4.08 4.501 5.784 4.979 ;
     RECT  34.8 3.685 35.208 5.029 ;
     RECT  5.1 4.979 5.784 5.077 ;
     RECT  7.8 2.151 8.112 5.077 ;
     RECT  9.12 4.933 10.812 5.077 ;
     RECT  29.4 2.151 29.712 5.077 ;
     RECT  34.8 5.029 35.352 5.077 ;
     RECT  7.8 5.077 10.812 5.123 ;
     RECT  31.344 4.837 33.096 5.171 ;
     RECT  26.7 2.151 27.012 5.173 ;
     RECT  13.2 3.877 13.704 5.365 ;
     RECT  0.192 5.365 0.216 5.555 ;
     RECT  13.2 5.365 13.848 5.605 ;
     RECT  18.6 4.595 18.912 5.605 ;
     RECT  20.688 4.501 21.612 5.747 ;
     RECT  7.8 5.123 9.144 5.939 ;
     RECT  13.2 5.605 13.992 5.941 ;
     RECT  24 2.151 24.312 6.133 ;
     RECT  15.9 2.151 16.212 6.229 ;
     RECT  18 5.605 18.912 6.229 ;
     RECT  18 6.229 19.848 6.323 ;
     RECT  32.1 5.171 33.096 6.323 ;
     RECT  4.08 4.979 4.104 6.565 ;
     RECT  5.1 5.077 6.312 6.565 ;
     RECT  7.8 5.939 9.096 6.565 ;
     RECT  26.496 5.173 27.012 6.659 ;
     RECT  34.8 5.077 36.024 6.661 ;
     RECT  10.5 5.123 10.812 6.805 ;
     RECT  21.3 5.747 21.612 6.805 ;
     RECT  28.56 5.077 29.712 6.899 ;
     RECT  29.088 6.899 29.712 7.139 ;
     RECT  15.9 6.229 16.536 7.189 ;
     RECT  13.056 5.941 13.992 7.331 ;
     RECT  15.9 7.189 17.112 7.331 ;
     RECT  32.1 6.323 32.412 7.381 ;
     RECT  13.056 7.331 13.944 7.475 ;
     RECT  34.8 6.661 36.456 7.475 ;
     RECT  4.08 6.565 6.312 7.477 ;
     RECT  36.432 7.475 36.456 7.619 ;
     RECT  7.488 6.565 9.096 7.765 ;
     RECT  10.224 6.805 10.812 7.765 ;
     RECT  0.144 7.765 0.168 7.955 ;
     RECT  4.08 7.477 6.36 7.957 ;
     RECT  7.488 7.765 10.812 7.957 ;
     RECT  18.6 6.323 19.848 7.957 ;
     RECT  31.008 7.381 32.412 8.003 ;
     RECT  13.2 7.475 13.944 8.051 ;
     RECT  2.4 2.151 2.712 8.101 ;
     RECT  4.08 7.957 10.812 8.101 ;
     RECT  17.76 7.957 19.848 8.245 ;
     RECT  21.168 6.805 21.612 8.245 ;
     RECT  2.4 8.101 10.812 8.291 ;
     RECT  29.4 7.139 29.712 9.109 ;
     RECT  4.56 8.291 10.812 9.155 ;
     RECT  23.328 6.133 24.312 9.155 ;
     RECT  4.56 9.155 6.36 9.203 ;
     RECT  7.8 9.155 10.812 9.203 ;
     RECT  7.8 9.203 9.096 9.251 ;
     RECT  29.184 9.109 29.712 9.299 ;
     RECT  32.1 8.003 32.412 9.349 ;
     RECT  4.56 9.203 6.312 9.491 ;
     RECT  32.1 9.349 32.52 9.491 ;
     RECT  12.192 8.821 12.216 9.541 ;
     RECT  13.2 8.051 13.848 9.541 ;
     RECT  26.7 6.659 27.012 9.589 ;
     RECT  12.192 9.541 13.848 9.779 ;
     RECT  15.9 7.331 16.212 9.829 ;
     RECT  17.76 8.245 21.612 9.875 ;
     RECT  0.144 8.917 0.168 10.115 ;
     RECT  31.008 8.003 31.032 10.165 ;
     RECT  32.1 9.491 32.412 10.165 ;
     RECT  34.8 7.475 35.112 10.165 ;
     RECT  37.5 2.151 37.812 10.165 ;
     RECT  17.76 9.875 19.368 10.213 ;
     RECT  20.736 9.875 21.612 10.307 ;
     RECT  12.336 9.779 13.848 10.309 ;
     RECT  4.752 9.491 6.312 10.355 ;
     RECT  10.5 9.203 10.812 10.453 ;
     RECT  7.8 9.251 8.28 10.789 ;
     RECT  34.8 10.165 35.4 10.835 ;
     RECT  26.7 9.589 27.48 10.883 ;
     RECT  37.008 10.165 37.812 10.883 ;
     RECT  12.336 10.309 14.232 10.931 ;
     RECT  33.792 9.061 33.816 10.931 ;
     RECT  53.7 2.151 54.012 10.981 ;
     RECT  34.8 10.835 35.112 11.221 ;
     RECT  53.7 10.981 54.696 11.267 ;
     RECT  17.664 10.213 19.368 11.269 ;
     RECT  7.8 10.789 9.096 11.413 ;
     RECT  10.5 10.453 11.304 11.507 ;
     RECT  12.336 10.931 13.512 11.507 ;
     RECT  29.4 9.299 29.712 11.653 ;
     RECT  61.8 2.151 62.112 11.701 ;
     RECT  7.8 11.413 9.144 11.747 ;
     RECT  4.944 10.355 6.312 11.797 ;
     RECT  28.752 11.653 29.712 11.797 ;
     RECT  61.8 11.701 62.76 11.843 ;
     RECT  17.328 11.269 19.368 11.939 ;
     RECT  28.656 11.797 29.712 11.941 ;
     RECT  20.784 10.307 21.612 12.179 ;
     RECT  7.8 11.747 9.096 12.227 ;
     RECT  17.328 11.939 18.912 12.227 ;
     RECT  4.944 11.797 6.696 12.325 ;
     RECT  4.56 12.325 6.696 12.373 ;
     RECT  7.8 12.227 8.28 12.373 ;
     RECT  26.7 10.883 27.012 12.517 ;
     RECT  34.656 11.221 35.112 12.517 ;
     RECT  4.56 12.373 8.28 12.563 ;
     RECT  13.104 11.507 13.512 12.997 ;
     RECT  31.008 10.165 32.412 13.045 ;
     RECT  33.6 12.517 33.624 13.045 ;
     RECT  30.816 13.045 33.624 13.091 ;
     RECT  4.56 12.563 8.112 13.427 ;
     RECT  34.656 12.517 35.352 13.477 ;
     RECT  15.312 9.829 16.212 13.573 ;
     RECT  24 9.155 24.312 13.621 ;
     RECT  15.312 13.573 17.16 13.715 ;
     RECT  26.016 12.517 27.012 13.715 ;
     RECT  28.464 11.941 29.712 13.715 ;
     RECT  23.808 13.621 24.312 13.861 ;
     RECT  4.56 13.427 6.696 14.099 ;
     RECT  30.816 13.091 33.096 14.099 ;
     RECT  34.656 13.477 35.88 14.291 ;
     RECT  32.1 14.099 33.096 14.339 ;
     RECT  12.24 12.997 13.512 14.965 ;
     RECT  21.3 12.179 21.612 15.253 ;
     RECT  10.5 11.507 10.812 15.301 ;
     RECT  4.944 14.099 6.696 15.349 ;
     RECT  7.8 13.427 8.112 15.349 ;
     RECT  18.24 12.227 18.912 15.491 ;
     RECT  28.848 13.715 29.712 15.491 ;
     RECT  10.5 15.301 10.92 15.877 ;
     RECT  12.24 14.965 13.992 15.877 ;
     RECT  15.312 13.715 16.212 15.925 ;
     RECT  30.816 14.099 30.84 16.019 ;
     RECT  34.8 14.291 35.88 16.019 ;
     RECT  4.944 15.349 8.112 16.021 ;
     RECT  23.28 13.861 24.312 16.115 ;
     RECT  23.808 16.115 24.312 16.307 ;
     RECT  4.848 16.021 8.112 16.405 ;
     RECT  4.848 16.405 8.616 16.501 ;
     RECT  4.08 16.501 8.616 16.549 ;
     RECT  18.6 15.491 18.912 16.549 ;
     RECT  32.1 14.339 33 16.835 ;
     RECT  24 16.307 24.312 16.837 ;
     RECT  18.6 16.549 19.224 16.885 ;
     RECT  29.4 15.491 29.712 16.981 ;
     RECT  4.08 16.549 9 17.029 ;
     RECT  15.312 15.925 17.064 17.029 ;
     RECT  21.072 15.253 21.612 17.029 ;
     RECT  10.5 15.877 13.992 17.077 ;
     RECT  29.28 16.981 29.712 17.077 ;
     RECT  24 16.837 25.08 17.123 ;
     RECT  15.312 17.029 17.112 17.125 ;
     RECT  4.08 17.029 9.096 17.219 ;
     RECT  29.088 17.077 29.712 17.219 ;
     RECT  15.312 17.125 17.208 17.267 ;
     RECT  29.232 17.219 29.712 17.267 ;
     RECT  18.6 16.885 19.416 17.413 ;
     RECT  28.032 17.317 28.056 17.459 ;
     RECT  4.224 17.219 9.096 17.507 ;
     RECT  18.6 17.413 19.512 17.605 ;
     RECT  32.1 16.835 32.412 17.605 ;
     RECT  10.32 17.077 13.992 17.651 ;
     RECT  7.68 17.507 9.096 17.747 ;
     RECT  7.68 17.747 9 17.843 ;
     RECT  7.8 17.843 9 17.891 ;
     RECT  4.224 17.507 6.696 17.939 ;
     RECT  4.224 17.939 5.88 18.179 ;
     RECT  20.496 17.029 21.612 18.181 ;
     RECT  26.7 13.715 27.012 18.181 ;
     RECT  15.312 17.267 16.212 18.227 ;
     RECT  4.224 18.179 5.412 18.371 ;
     RECT  37.5 10.883 37.812 18.757 ;
     RECT  20.496 18.181 21.72 18.803 ;
     RECT  10.32 17.651 12.024 18.851 ;
     RECT  21.3 18.803 21.72 18.851 ;
     RECT  29.28 17.267 29.712 18.851 ;
     RECT  18.48 17.605 19.512 18.947 ;
     RECT  34.8 16.019 35.208 18.947 ;
     RECT  15.9 18.227 16.212 18.949 ;
     RECT  4.272 18.371 5.412 18.995 ;
     RECT  4.848 18.995 5.412 19.237 ;
     RECT  26.7 18.181 27.816 19.427 ;
     RECT  31.968 17.605 32.412 19.427 ;
     RECT  10.32 18.851 11.928 19.523 ;
     RECT  18.6 18.947 19.512 19.525 ;
     RECT  7.8 17.891 8.112 19.669 ;
     RECT  37.056 18.757 37.812 19.813 ;
     RECT  13.2 17.651 13.992 19.861 ;
     RECT  13.104 19.861 13.992 20.195 ;
     RECT  30.864 16.213 30.888 20.533 ;
     RECT  26.7 19.427 27.624 20.579 ;
     RECT  30.768 20.533 30.888 20.579 ;
     RECT  36.48 19.813 37.812 20.579 ;
     RECT  4.848 19.237 5.592 20.627 ;
     RECT  30.768 20.579 30.792 20.723 ;
     RECT  7.8 19.669 8.232 20.869 ;
     RECT  40.2 2.151 40.512 20.869 ;
     RECT  29.4 18.851 29.712 20.917 ;
     RECT  24 17.123 24.312 21.013 ;
     RECT  25.296 20.581 25.32 21.013 ;
     RECT  29.28 20.917 29.712 21.107 ;
     RECT  36.768 20.579 37.812 21.157 ;
     RECT  36.768 21.157 38.232 21.443 ;
     RECT  7.8 20.869 8.904 21.541 ;
     RECT  15.9 18.949 16.344 21.589 ;
     RECT  24 21.013 25.32 21.683 ;
     RECT  39.744 20.869 40.512 21.683 ;
     RECT  28.08 20.629 28.2 21.875 ;
     RECT  4.848 20.627 5.412 22.259 ;
     RECT  10.32 19.523 11.784 22.453 ;
     RECT  18.6 19.525 19.992 22.645 ;
     RECT  10.224 22.453 11.784 22.741 ;
     RECT  13.2 20.195 13.992 22.741 ;
     RECT  40.2 21.683 40.512 22.741 ;
     RECT  7.584 21.541 8.904 22.787 ;
     RECT  5.1 22.259 5.412 22.789 ;
     RECT  15.9 21.589 17.16 23.221 ;
     RECT  18.6 22.645 20.184 23.221 ;
     RECT  21.3 18.851 21.612 23.221 ;
     RECT  10.224 22.741 13.992 23.267 ;
     RECT  0.144 23.077 0.168 23.363 ;
     RECT  10.224 23.267 11.4 23.363 ;
     RECT  18.48 23.221 20.184 23.363 ;
     RECT  12.528 23.267 13.992 23.411 ;
     RECT  5.1 22.789 5.592 23.555 ;
     RECT  40.032 22.741 40.512 23.555 ;
     RECT  26.7 20.579 27.012 23.845 ;
     RECT  28.176 21.875 28.2 23.845 ;
     RECT  7.584 22.787 8.112 23.891 ;
     RECT  26.7 23.845 28.2 23.893 ;
     RECT  29.4 21.107 29.712 23.893 ;
     RECT  15.9 23.221 17.448 23.987 ;
     RECT  18.48 23.363 19.992 24.325 ;
     RECT  34.8 18.947 35.112 24.325 ;
     RECT  36.768 21.443 37.812 24.325 ;
     RECT  15.9 23.987 16.344 24.467 ;
     RECT  10.32 23.363 11.4 24.469 ;
     RECT  13.2 23.411 13.992 24.469 ;
     RECT  17.664 24.325 19.992 24.563 ;
     RECT  21.3 23.221 22.104 24.659 ;
     RECT  17.664 24.563 19.416 24.851 ;
     RECT  21.3 24.659 21.612 25.045 ;
     RECT  25.68 23.893 25.704 25.139 ;
     RECT  5.1 23.555 5.412 25.189 ;
     RECT  17.664 24.851 18.912 25.475 ;
     RECT  7.68 23.891 8.112 25.715 ;
     RECT  24 21.683 24.552 25.715 ;
     RECT  36.768 24.325 38.04 25.715 ;
     RECT  18.6 25.475 18.912 25.813 ;
     RECT  26.7 23.893 29.712 25.859 ;
     RECT  26.7 25.859 27.384 26.051 ;
     RECT  34.224 24.325 35.112 26.051 ;
     RECT  9.552 24.469 11.4 26.243 ;
     RECT  28.896 25.859 29.712 26.243 ;
     RECT  12.528 24.469 13.992 26.387 ;
     RECT  20.592 25.045 21.612 26.485 ;
     RECT  9.552 26.243 11.256 26.531 ;
     RECT  13.2 26.387 13.992 26.677 ;
     RECT  5.1 25.189 5.976 26.771 ;
     RECT  20.544 26.485 21.612 26.819 ;
     RECT  34.272 26.051 35.112 26.819 ;
     RECT  13.2 26.677 14.184 27.203 ;
     RECT  18.6 25.813 19.08 27.203 ;
     RECT  26.7 26.051 27.144 27.395 ;
     RECT  2.4 8.291 2.712 27.819 ;
     RECT  5.1 26.771 5.412 27.819 ;
     RECT  7.8 25.715 8.112 27.819 ;
     RECT  10.5 26.531 11.256 27.819 ;
     RECT  13.2 27.203 13.992 27.819 ;
     RECT  15.9 24.467 16.212 27.819 ;
     RECT  18.6 27.203 18.912 27.819 ;
     RECT  21.3 26.819 21.612 27.819 ;
     RECT  24 25.715 24.312 27.819 ;
     RECT  26.7 27.395 27.012 27.819 ;
     RECT  29.4 26.243 29.712 27.819 ;
     RECT  32.1 19.427 32.412 27.819 ;
     RECT  34.8 26.819 35.112 27.819 ;
     RECT  37.5 25.715 37.812 27.819 ;
     RECT  40.2 23.555 40.512 27.819 ;
     RECT  42.9 2.151 43.212 27.819 ;
     RECT  45.6 2.151 45.912 27.819 ;
     RECT  48.3 2.151 48.612 27.819 ;
     RECT  51 2.151 51.312 27.819 ;
     RECT  53.7 11.267 54.012 27.819 ;
     RECT  56.4 2.151 56.712 27.819 ;
     RECT  59.1 2.151 59.412 27.819 ;
     RECT  61.8 11.843 62.112 27.819 ;
     RECT  2.592 27.819 2.712 27.833 ;
     RECT  5.292 27.819 5.412 27.833 ;
     RECT  7.992 27.819 8.112 27.833 ;
     RECT  10.692 27.819 11.256 27.833 ;
     RECT  13.392 27.819 13.992 27.833 ;
     RECT  16.092 27.819 16.212 27.833 ;
     RECT  18.792 27.819 18.912 27.833 ;
     RECT  21.492 27.819 21.612 27.833 ;
     RECT  24.192 27.819 24.312 27.833 ;
     RECT  26.892 27.819 27.012 27.833 ;
     RECT  29.592 27.819 29.712 27.833 ;
     RECT  32.292 27.819 32.412 27.833 ;
     RECT  34.992 27.819 35.112 27.833 ;
     RECT  37.692 27.819 37.812 27.833 ;
     RECT  40.392 27.819 40.512 27.833 ;
     RECT  43.092 27.819 43.212 27.833 ;
     RECT  45.792 27.819 45.912 27.833 ;
     RECT  48.492 27.819 48.612 27.833 ;
     RECT  51.192 27.819 51.312 27.833 ;
     RECT  53.892 27.819 54.012 27.833 ;
     RECT  56.592 27.819 56.712 27.833 ;
     RECT  59.292 27.819 59.412 27.833 ;
     RECT  61.992 27.819 62.112 27.833 ;
     RECT  11.232 27.833 11.256 29.699 ;
     RECT  13.968 27.833 13.992 30.131 ;
  END
END qfd_landh0_128_EW_65x30
END LIBRARY
